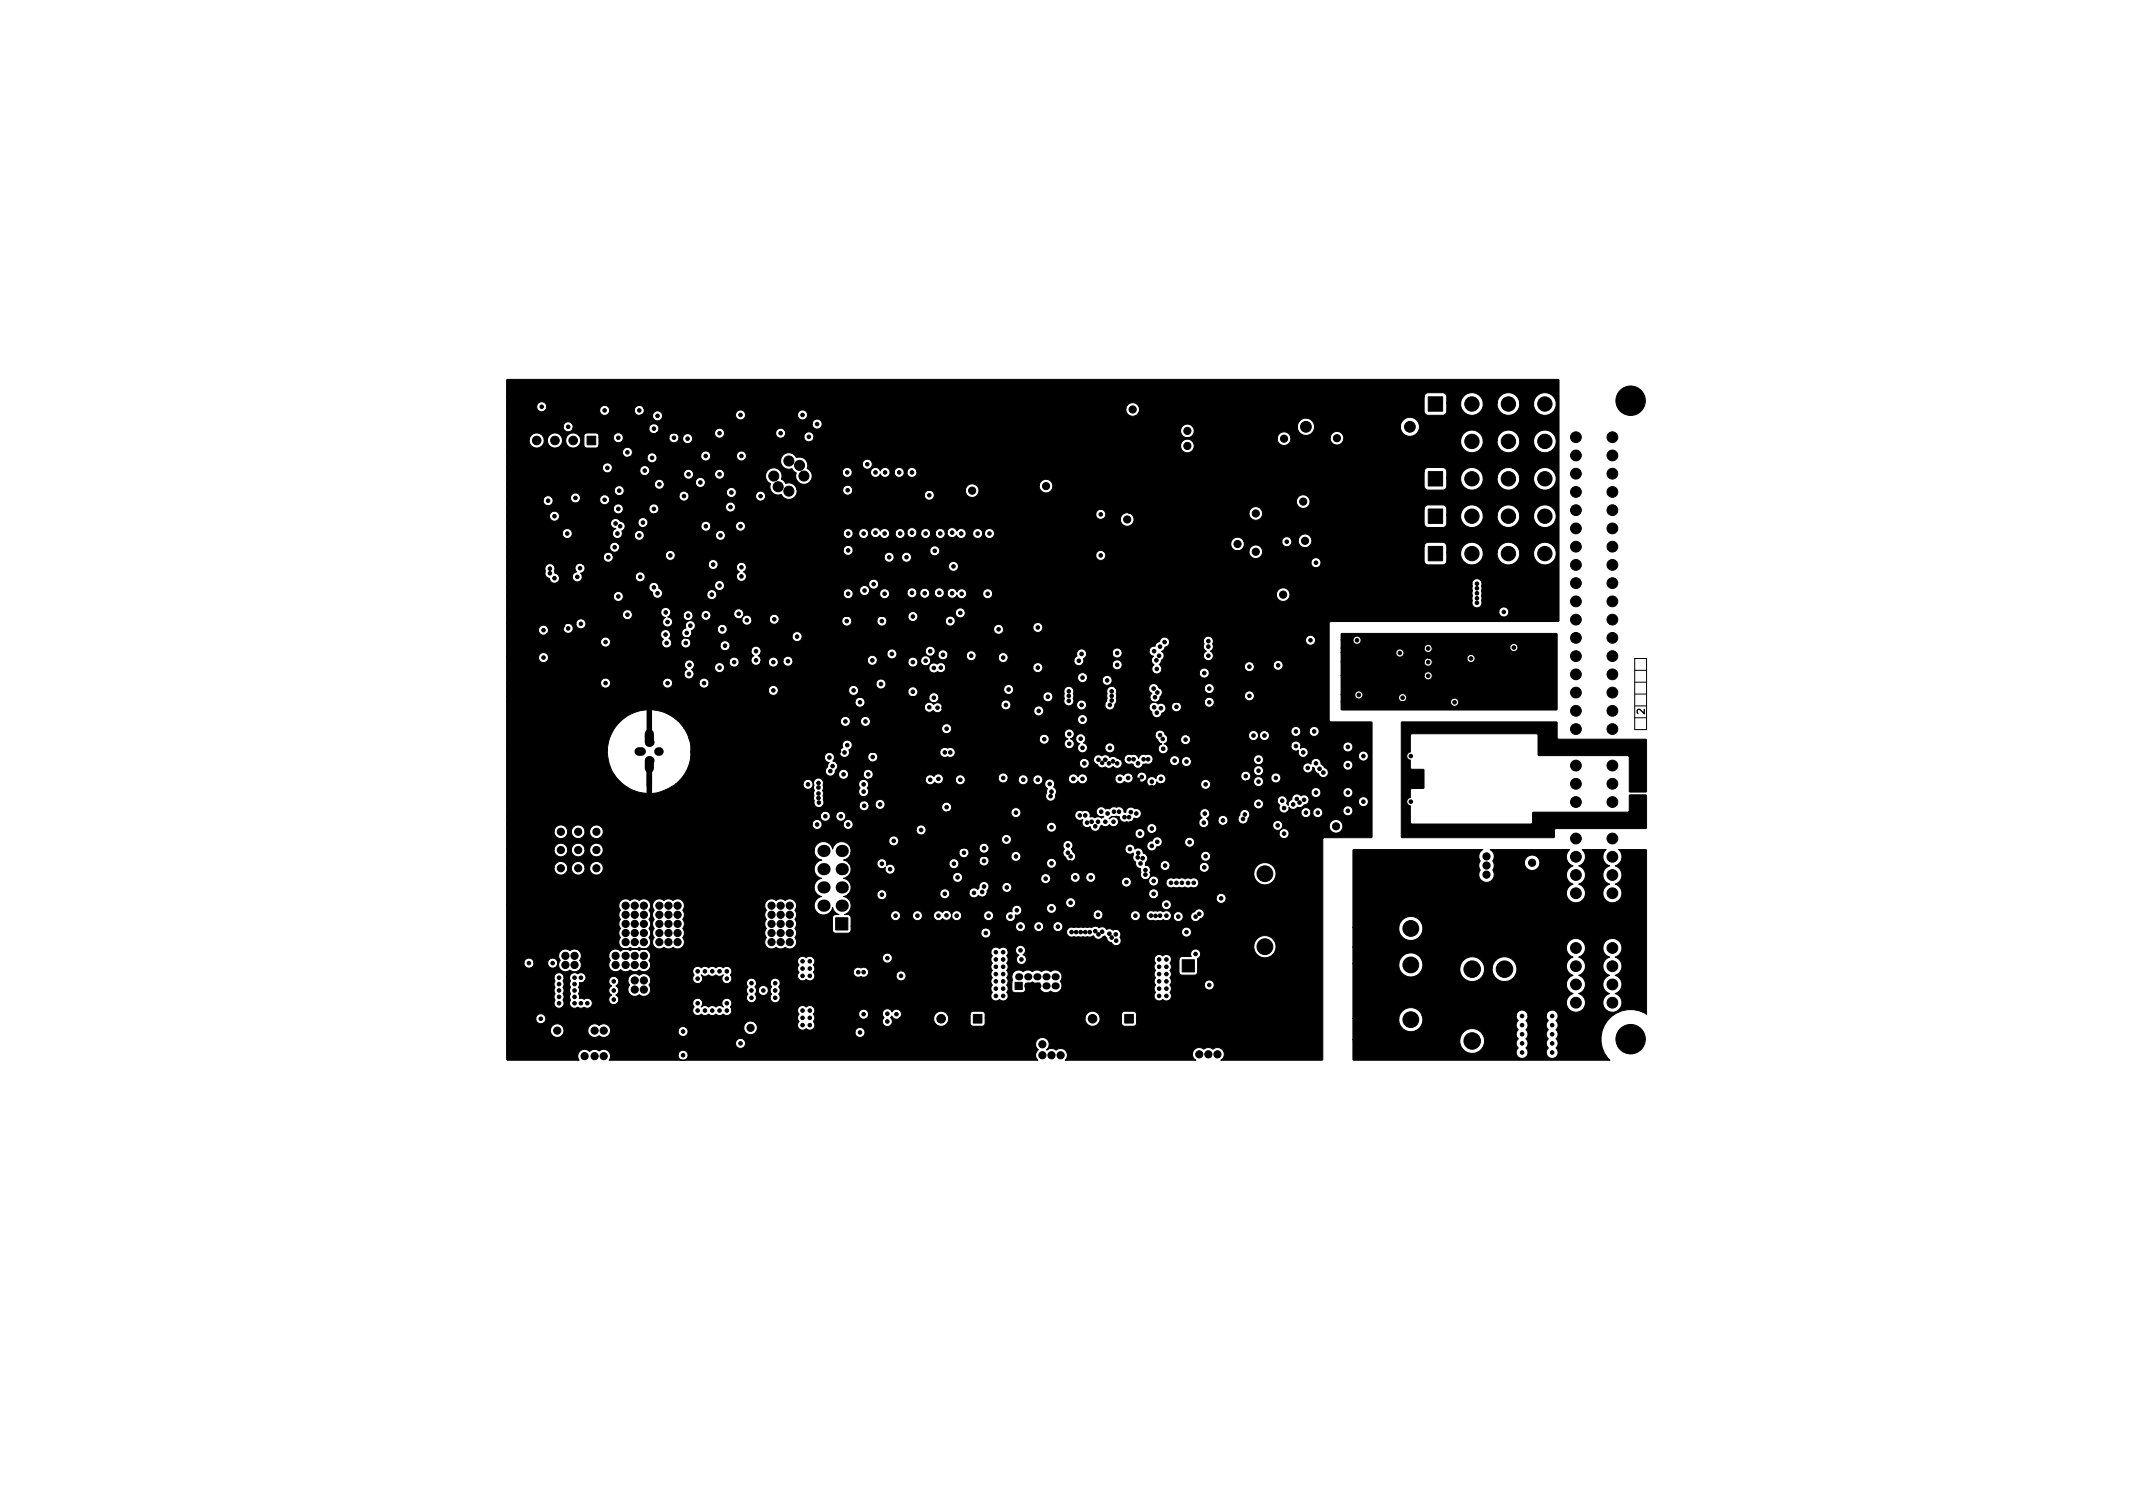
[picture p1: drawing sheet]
<svg xmlns="http://www.w3.org/2000/svg" width="297mm" height="210mm" viewBox="0 0 297 210" stroke-linecap="round" stroke-linejoin="round" font-family="sans-serif">
<defs><g id="words">
<text font-size="1.4" x="229" y="99.4" transform="rotate(-90 229 99.4)">2</text>
</g></defs>
<g fill="#000" stroke="#000" stroke-width=".14">
<path d="M198.9 55.3h2v2h-2zM70.5 52.9l.1-.1h146.4l.1 .1v33.6h-.1h-31.7l-.2 .2v13.6l.2 .2h5.7l.1 .1v16h-.1h-6.6l-.2 .2v30.7l-.1 .1h-14.1a.97 .97 0 0 0 .3-1.4 .97 .97 0 0 0-1.4-.1 1.05 1.05 0 0 0-1.3 0 .95 .95 0 0 0-1.4 .2 .95 .95 0 0 0 .3 1.3h-18.2l.1-.1a.97 .97 0 0 0-.1-1.3 .97 .97 0 0 0-1.3 0 1.05 1.05 0 0 0-1.2 0v-.1a.95 .95 0 0 0 0-1.4 .95 .95 0 0 0-1.3 .1 .95 .95 0 0 0 .1 1.4 .94 .94 0 0 0-.1 1.4h-59.7l.2-.3v-.4h9.4v.1a.7 .7 0 0 0 1.1 .5 .7 .7 0 0 0 0-1.2 .7 .7 0 0 0-1.1 .6h-9.4v-.1a1 1 0 0 0-1.6-.5 .94 .94 0 0 0-1.3 .1 .95 .95 0 0 0-1.3-.1 .95 .95 0 0 0-.1 1.3h-10.1l-.1-.1v-2.3h31.9a.7 .7 0 0 0 1 .7 .7 .7 0 0 0 .2-1.1 .7 .7 0 0 0-1.1 .3l-.1 .1h-31.9v-1.8h6.2a.95 .95 0 0 0 .9 1.1 .95 .95 0 0 0 .9-1.1h3.4v.2a.99 .99 0 0 0 1.6 .6 .95 .95 0 0 0 1 .2 .95 .95 0 0 0 .5-.8h9.4v.1a.7 .7 0 0 0 1.1 .5 .7 .7 0 0 0 0-1.2h8.1v.2a.95 .95 0 0 0 .7 .8 .95 .95 0 0 0 1-.3h13.8v.1a.7 .7 0 0 0 1 .6 .7 .7 0 0 0 0-1.2 .7 .7 0 0 0-1 .5h-13.8l.1-.1a.95 .95 0 0 0-.6-1.4 .95 .95 0 0 0-1.2 .8h-8.1a.7 .7 0 0 0-1.1 .6h-9.4v-.2a.99 .99 0 0 0-1.6-.6 .95 .95 0 0 0-1.5 .6h-3.4v-.2a.95 .95 0 0 0-1-.6 .95 .95 0 0 0-.8 .8h-6.2v-1.6h4.1v.1a.7 .7 0 0 0 1.1 .5 .7 .7 0 0 0 0-1.1 .7 .7 0 0 0-1.1 .5h-4.1v-5.7h6.7v.1a.53 .53 0 0 1 0 .8l.1 .5a.71 .71 0 0 0 0 .9 .7 .7 0 0 0 0 .9 .7 .7 0 0 0 .1 .9 .7 .7 0 0 0 .9 0 .7 .7 0 0 0 .1-1 .7 .7 0 0 0 0-.8 .7 .7 0 0 0 0-.9 .7 .7 0 0 0 0-.9l.1-.5h.8v.1a.53 .53 0 0 1 0 .8l.2 .5a.71 .71 0 0 0 0 .9 .7 .7 0 0 0 0 .9 .7 .7 0 0 0 0 .9 .7 .7 0 0 0 1 0 .7 .7 0 0 0 .8 0 .7 .7 0 0 0 1 0 .7 .7 0 0 0 0-1 .7 .7 0 0 0-1 0l-.3-.2h-.3v-.3l-.2-.3a.71 .71 0 0 0 0-.9l.2-.4v-.3a.69 .69 0 0 0 .7-.2h3.4l.1 .4 .3 .3a.69 .69 0 0 0-.4 .6 .69 .69 0 0 0 .4 .7 .7 .7 0 0 0-.3 1 .7 .7 0 0 0 1.1 0h10.5v.3l.2 .3a.7 .7 0 0 0 0 1 .7 .7 0 0 0 1 0 .69 .69 0 0 0 1 0 .69 .69 0 0 0 1 0 .69 .69 0 0 0 1 0 .7 .7 0 0 0 .8 .1 .7 .7 0 0 0 .4-.7h9.2v.3l.2 .3a.69 .69 0 0 0 0 1 .7 .7 0 0 0 0 1 .7 .7 0 0 0 1 0 .7 .7 0 0 0 1 0 .7 .7 0 0 0 0-1 .69 .69 0 0 0 0-1h6.3v.1a.7 .7 0 0 0 .8 .6 .7 .7 0 0 0 .6-.8h1.9v.3l.2 .3a.7 .7 0 0 0 0 1 .7 .7 0 0 0 1 0 .7 .7 0 0 0-.1-1l.2-.2a.69 .69 0 0 0 1.1 .3h4.7v.2a1.05 1.05 0 0 0 1.4 .8 1.05 1.05 0 0 0 .5-1.5h3.2v1.2a.45 .45 0 0 0 .4 .4l1.5-.1 .2-.3v-.7h13.9v.2a1.05 1.05 0 0 0 1.4 .8 1.05 1.05 0 0 0 .5-1.5h3.2v1.2a.45 .45 0 0 0 .4 .4h1.2l.3-.1 .2-.3v-1.2a.45 .45 0 0 0-.5-.5h-1.3l-.2 .1-.1 .4h-3.2a1.05 1.05 0 0 0-1.1-.5 1.05 1.05 0 0 0-.8 1h-13.9v-.5a.45 .45 0 0 0-.5-.5h-1.2l-.3 .1-.1 .4h-3.2a1.05 1.05 0 0 0-1.1-.5 1.05 1.05 0 0 0-.8 1h-4.7l.1-.1a.7 .7 0 0 0-.2-1.1 .7 .7 0 0 0-1 .3 .7 .7 0 0 0-.7-.4 .7 .7 0 0 0-.6 .6h-1.9l-.1-.1a.7 .7 0 0 0-.7-.5 .7 .7 0 0 0-.6 .7h-6.3l.1-.2a.7 .7 0 0 0-.2-.9 .7 .7 0 0 0-.9 .1 .7 .7 0 0 0-.8-.2 .7 .7 0 0 0-.4 .6h-9.2l-.2-.4 .1-.1a.7 .7 0 0 0-.1-.9 .7 .7 0 0 0-1 0 .7 .7 0 0 0 0 1 .78 .78 0 0 0-1 0 .69 .69 0 0 0-1 0 .78 .78 0 0 0-1.1 0 .7 .7 0 0 0-.1-1.1 .7 .7 0 0 0-1 .5h-10.5l.1-.1a.69 .69 0 0 0-.3-.9 .69 .69 0 0 0 .4-.7 .69 .69 0 0 0-.4-.6 .69 .69 0 0 0 .3-.9h1.3l.1 .4 .2 .4a.97 .97 0 0 0 0 1.3 .97 .97 0 0 0 1.4 0 .97 .97 0 0 0 1.3-.1 .97 .97 0 0 0 0-1.3 .97 .97 0 0 0-.1-1.3 .97 .97 0 0 0-1.3 0 .95 .95 0 0 0-1.6 .6h-1.3v-.1a.7 .7 0 0 0-.8-.3 .7 .7 0 0 0-.5 .6h-3.4l.1-.1a.7 .7 0 0 0-.2-.9 .7 .7 0 0 0-.8 0 .7 .7 0 0 0-1.2 .5h-.8v-.2a.7 .7 0 0 0-.7-.5 .7 .7 0 0 0-.6 .7h-6.7v-2.1h2.5v.2a.7 .7 0 0 0 .7 .6 .7 .7 0 0 0 .7-.8h1.9v.2a.7 .7 0 0 0 1 .5 .7 .7 0 0 0 0-1.2 .7 .7 0 0 0-1 .5h-1.9l-.1-.1a.7 .7 0 0 0-.7-.5 .7 .7 0 0 0-.6 .6h-2.5v-1h7.3v.4l.2 .3a.97 .97 0 0 0 .1 1.3 .97 .97 0 0 0 1.3 .1 .97 .97 0 0 0 1.3-.1 .97 .97 0 0 0 0-1.3l.2-.3 .1-.4h3.8v.4l.2 .3a.95 .95 0 0 0 .1 1.4 .95 .95 0 0 0 1.3-.1 1.04 1.04 0 0 0 1.4 .1 1.05 1.05 0 0 0 1.3 0l.5 .2 .5-.1h6.4v.3l.2 .3h-.1a.7 .7 0 0 0 .1 1 .7 .7 0 0 0 1-.1 .7 .7 0 0 0-.1-.9 .78 .78 0 0 0 1.1-.1 .69 .69 0 0 0 1 0 .78 .78 0 0 0 1 .1 .69 .69 0 0 0 0 .9 .69 .69 0 0 0 .9 .1h2.4v.3l.2 .3a.69 .69 0 0 0 0 1 .7 .7 0 0 0-.1 1 .7 .7 0 0 0 1 0 .7 .7 0 0 0 0-1l.2-.3v-.3h.3a.7 .7 0 0 0 .9 .8 .7 .7 0 0 0 .3-1.2 .7 .7 0 0 0-1.2 .3v.1h-.3l-.2-.4 .2-.3v-.3h2v.3l.2 .3-.1 .1a.69 .69 0 0 0 .1 .9 .7 .7 0 0 0 0 1 .7 .7 0 0 0 .9 0 .7 .7 0 0 0 0-1 .69 .69 0 0 0 0-1 .7 .7 0 0 0-.1-1.1 .7 .7 0 0 0-1 .5h-2v-.1a.7 .7 0 0 0-.7-.5 .7 .7 0 0 0-.6 .6h-2.3a.69 .69 0 0 0 0-1 .7 .7 0 0 0 0-1 .7 .7 0 0 0-1 0 .69 .69 0 0 0-1 0 .69 .69 0 0 0-1 0 .69 .69 0 0 0-1 0 .7 .7 0 0 0-.8-.2 .7 .7 0 0 0-.4 .6h-6.4l.2-.1a.94 .94 0 0 0 .1-1.3h20.7v.3l.2 .3a.69 .69 0 0 0 0 1 .7 .7 0 0 0 0 1 .7 .7 0 0 0 1 0 .7 .7 0 0 0 1 0 .7 .7 0 0 0 0-1l5.5-.1v.1a.76 .76 0 0 0 1.1 .6 .7 .7 0 0 0 .9-.2h4v.2a.7 .7 0 0 0 1 .5 .7 .7 0 0 0 0-1.2 .7 .7 0 0 0-1 .5h-4l.1-.1a.73 .73 0 0 0-.2-.9 .73 .73 0 0 0-.9 0 .7 .7 0 0 0-1 .5h-5.5l.2-.5-.2-.4v-.1a.69 .69 0 0 0-.1-1h9.7v.2a.7 .7 0 0 0 1 .5 .7 .7 0 0 0 0-1.2 .7 .7 0 0 0-1 .5h-9.7a.69 .69 0 0 0-.9 .1 .7 .7 0 0 0-.8-.2 .7 .7 0 0 0-.4 .6h-20.7a1.1 1.1 0 0 0 0-1.3h47.6v.3l.2 .3a.69 .69 0 0 0 0 1 .69 .69 0 0 0 0 1 .69 .69 0 0 0 0 1 .69 .69 0 0 0 0 1.1 .69 .69 0 0 0 0 1 .7 .7 0 0 0 0 1 .7 .7 0 0 0 1 0 .7 .7 0 0 0 1 0 .7 .7 0 0 0 0-1 .69 .69 0 0 0 0-1l.2-.4h.5v1a.45 .45 0 0 0 .5 .4h1l.3-.1 .1-.2v-1a1.15 1.15 0 0 0 1-.2l.5 .3 .5-.1a.98 .98 0 0 0 .3 1.1 .98 .98 0 0 0 1.2 0 .97 .97 0 0 0 1.3-.1 .97 .97 0 0 0 .1-1.3 .97 .97 0 0 0-.1-1.3 .97 .97 0 0 0-1.3 0 1.05 1.05 0 0 0-1.3 0 1.05 1.05 0 0 0-1.3 0 1.05 1.05 0 0 0-1.2 0 .99 .99 0 0 0-1.3 0 .99 .99 0 0 0-.2 1.2l-.1 .3h-.5v-.4l-.2-.3a.69 .69 0 0 0 0-1 .69 .69 0 0 0 0-1 .69 .69 0 0 0 0-1l.2-.4-.1-.4h1.1l.1 .4 .4 .3-.1 .1a.7 .7 0 0 0 .2 1.1 .7 .7 0 0 0 .9-.7h17.8v.3l.2 .3a.69 .69 0 0 0 0 1 .69 .69 0 0 0 0 1 .69 .69 0 0 0 0 1.1 .69 .69 0 0 0 0 1 .7 .7 0 0 0 0 1 .7 .7 0 0 0 1 0 .7 .7 0 0 0 1 0 .7 .7 0 0 0 0-1 .69 .69 0 0 0 0-1l4.8-.1v.1a.7 .7 0 0 0 1.1 .5 .7 .7 0 0 0 0-1.1 .7 .7 0 0 0-1.1 .5h-4.7l.1-.5-.2-.5h.1a.69 .69 0 0 0-.1-1 .69 .69 0 0 0 0-1l.2-.5h1.1v1.7l.1 .4 .3 .1h1.7a.45 .45 0 0 0 .5-.5v-1.7a.71 .71 0 0 0 .4-.9 .71 .71 0 0 0-.9-.5 .71 .71 0 0 0-.5 .8l.1 .2h-1.4l-.2 .2-.1 .2h-1.1a.69 .69 0 0 0-.4-.6 .69 .69 0 0 0-.8 .1 .7 .7 0 0 0-.7-.2 .7 .7 0 0 0-.5 .6h-17.8l-.1-.3-.3-.3h.1a.7 .7 0 0 0-.2-1.2 .7 .7 0 0 0-1 .6h-1.1a.69 .69 0 0 0-1.1-.2 .7 .7 0 0 0-.7-.2 .7 .7 0 0 0-.5 .6h-47.6a1.04 1.04 0 0 0-1.4-.1 1.05 1.05 0 0 0-1.3 0 .94 .94 0 0 0-1.3 .1 .95 .95 0 0 0-1-.3 .95 .95 0 0 0-.6 .8h-3.8l-.1-.2a1 1 0 0 0-1.6-.4 .95 .95 0 0 0-1.5 .6h-7.3v-7h15.7v.4l.2 .3a1.04 1.04 0 0 0 0 1.3 1.05 1.05 0 0 0 0 1.3 1.05 1.05 0 0 0 0 1.3 .97 .97 0 0 0 .1 1.3 .97 .97 0 0 0 1.3 0 1.05 1.05 0 0 0 1.3 0 .97 .97 0 0 0 1.3-.1 .97 .97 0 0 0 0-1.3 1.05 1.05 0 0 0 0-1.3 1.05 1.05 0 0 0 0-1.2 1.05 1.05 0 0 0 0-1.3l.2-.3v-.4h.3v.4l.2 .3a1.04 1.04 0 0 0 0 1.3 1.05 1.05 0 0 0 0 1.3 1.05 1.05 0 0 0 0 1.3 .97 .97 0 0 0 .1 1.3 .97 .97 0 0 0 1.3 0 1.05 1.05 0 0 0 1.3 0 .97 .97 0 0 0 1.3-.1 .97 .97 0 0 0 0-1.3 1.05 1.05 0 0 0 0-1.3 1.05 1.05 0 0 0 0-1.2 1.05 1.05 0 0 0 0-1.3l.2-.3v-.4h11.2v.4l.2 .3a1.04 1.04 0 0 0 0 1.3 1.05 1.05 0 0 0 0 1.3 1.05 1.05 0 0 0 0 1.3 .97 .97 0 0 0 .1 1.3 .97 .97 0 0 0 1.3 0 1.05 1.05 0 0 0 1.3 0 .97 .97 0 0 0 1.3-.1 .97 .97 0 0 0 0-1.3 1.05 1.05 0 0 0 0-1.3 1.05 1.05 0 0 0 0-1.2 1.05 1.05 0 0 0 0-1.3 .97 .97 0 0 0-.1-1.3 .97 .97 0 0 0-1.3 0 1.05 1.05 0 0 0-1.3 0 .95 .95 0 0 0-1.5 .6h-11.2v-.2a1 1 0 0 0-1.6-.4 1.05 1.05 0 0 0-1.3 0 .95 .95 0 0 0-1.5 .6h-.3v-.2a1 1 0 0 0-1.6-.4 1.05 1.05 0 0 0-1.3 0 .95 .95 0 0 0-1.5 .6h-15.7v-5.2h6.7v.2a.95 .95 0 0 0 1 .8 .95 .95 0 0 0 .8-1h.6v.2a.95 .95 0 0 0 1 .8 .95 .95 0 0 0 .9-1h.6v.2a.95 .95 0 0 0 1.5 .7 .95 .95 0 0 0 0-1.6 .95 .95 0 0 0-1.5 .7h-.6l-.1-.2a.95 .95 0 0 0-1-.6 .95 .95 0 0 0-.8 .8h-.6v-.2a.95 .95 0 0 0-1-.6 .95 .95 0 0 0-.8 .8h-6.7v-2.5h6.7v.2a.95 .95 0 0 0 1 .8 .95 .95 0 0 0 .8-1h.6v.2a.95 .95 0 0 0 1 .8 .95 .95 0 0 0 .9-1h.6v.2a.95 .95 0 0 0 1 .8 .95 .95 0 0 0 .9-.9h29.4l.1 .7 .4 .4 .5 .3h-.1a1.3 1.3 0 0 0-.9 1.3 1.3 1.3 0 0 0 1 1.2 1.29 1.29 0 0 0-1 1.3 1.29 1.29 0 0 0 1 1.2 1.3 1.3 0 0 0-.6 2.2 1.3 1.3 0 0 0 2.2-.6l.2 .5 .6 .4-.6 .1-.2 .2-.1 1.9a.45 .45 0 0 0 .5 .4h1.7l.2-.1h18.3a.7 .7 0 0 0 .9 .8 .7 .7 0 0 0 .3-1.2 .7 .7 0 0 0-1.2 .3v.1h-18.3l.2-.2v-.6h22.9v.1a.7 .7 0 0 0 .8 .6 .7 .7 0 0 0 .6-.7h1.2v.1a.7 .7 0 0 0 .7 .6 .7 .7 0 0 0 .6-.7h1.3v.1a.7 .7 0 0 0 .8 .6h1.1v.2a.7 .7 0 0 0 1 .5l2.3 .1 .4-.2a.75 .75 0 0 0 .7 .5 .75 .75 0 0 0 .7-.4l.3-.1 .2 .3a.84 .84 0 0 0 .7 .7l.2 .2 .4 .2h19.2a1.55 1.55 0 0 0 2.1 1.6 1.55 1.55 0 0 0 .5-2.6 1.55 1.55 0 0 0-2.5 .7l-.1 .3h-19a.69 .69 0 0 0 .4-1.2l.1-.3-.1-.5h8.5a.7 .7 0 0 0 1 .7 .7 .7 0 0 0 .2-1.1 .7 .7 0 0 0-1.1 .3l-.1 .1h-8.5a.69 .69 0 0 0-1-.2 .68 .68 0 0 0-.9-.1 .69 .69 0 0 0-1.1-.2 .69 .69 0 0 0-1 0l-2.2-.1-.3 .1a.7 .7 0 0 0-1 .5h-1.1h.1a.7 .7 0 0 0 .3-1.2 .7 .7 0 0 0-1.2 .5h-1.3v-.2a.7 .7 0 0 0-.7-.5 .7 .7 0 0 0-.6 .7h-1.2v-.2a.7 .7 0 0 0-.8-.5 .7 .7 0 0 0-.6 .7h-22.9v-1.3l-.2-.3h5.7a.7 .7 0 0 0 .7 .8 .7 .7 0 0 0 .7-.8h1.7v.2a.7 .7 0 0 0 .7 .6 .7 .7 0 0 0 .7-.8h1.5v.2a.7 .7 0 0 0 .5 .6 .7 .7 0 0 0 .8-.3 .72 .72 0 0 0 .8 .2 .72 .72 0 0 0 .4-.7 .7 .7 0 0 0 .7 .8 .7 .7 0 0 0 .7-.8h3.1v.2a.7 .7 0 0 0 .7 .6 .7 .7 0 0 0 .7-.6h1.6v.1a.7 .7 0 0 0 .9 .6 .7 .7 0 0 0 .5-.9h.3l.3-.1h10.2v.1a.7 .7 0 0 0 .7 .7 .7 .7 0 0 0 .7-.7h3.8v.2a.7 .7 0 0 0 .8 .6 .7 .7 0 0 0 .6-.8h.8v.2a.71 .71 0 0 0 1 .5l.4 .1 .3-.1a.7 .7 0 0 0 .7-.1 .7 .7 0 0 0 1.1-.4h.3v.1a.7 .7 0 0 0 .8 .6 .7 .7 0 0 0 .6-.7h1v.1a.74 .74 0 0 0 .6 .6 .74 .74 0 0 0 .8-.4 .7 .7 0 0 0 .3-1.1 .7 .7 0 0 0-1.1 .1l-.4 .3-.2 .4h-1a.7 .7 0 0 0-.7-.7 .7 .7 0 0 0-.7 .7h-.3v-.2a.7 .7 0 0 0-1.1-.4l-.4-.2-1 .1a.7 .7 0 0 0-1 .5h-.8v-.1a.7 .7 0 0 0-.8-.5 .7 .7 0 0 0-.6 .6h-3.8v-.1a.7 .7 0 0 0-.7-.6 .7 .7 0 0 0-.7 .6h-10.2l.3-.4-.1-.5h3.5a.7 .7 0 0 0 1 .7 .7 .7 0 0 0 .2-1.1 .7 .7 0 0 0-1.1 .3l-.1 .1h-3.5a.7 .7 0 0 0-.9-.3 .7 .7 0 0 0-.3 .9 .69 .69 0 0 0-1 .6h-1.6v-.2a.7 .7 0 0 0-.7-.6 .7 .7 0 0 0-.7 .6h-3.1v-.1a.72 .72 0 0 0-.8-.5 .72 .72 0 0 0-.6 .6 .69 .69 0 0 0-.5-.6 .69 .69 0 0 0-.8 .3 .7 .7 0 0 0-.7-.3 .7 .7 0 0 0-.5 .6h-1.5l-.1-.1a.7 .7 0 0 0-.7-.5 .7 .7 0 0 0-.6 .6h-1.7v-.1a.7 .7 0 0 0-.8-.5 .7 .7 0 0 0-.6 .6h-5.7l-.7-.1a1.29 1.29 0 0 0 .8-1.7h30v.2a.7 .7 0 0 0 .6 .6 .7 .7 0 0 0 .8-.5h11.9v.1a.7 .7 0 0 0 1.1 .6 .7 .7 0 0 0 0-1.2 .7 .7 0 0 0-1.1 .5h-11.9a.7 .7 0 0 0-.6-.9 .7 .7 0 0 0-.8 .6h-30l-.4-.5-.5-.3 .6-.3h4a.7 .7 0 0 0 .8 .8 .7 .7 0 0 0 .6-.9h7.4v.1a.7 .7 0 0 0 .8 .6 .7 .7 0 0 0 .5-.8h2.7v.1a.7 .7 0 0 0 .6 .6 .7 .7 0 0 0 .8-.3 .69 .69 0 0 0 1.2-.3h22.5v.1a.69 .69 0 0 0 1.1 .5h8.3v.2a.7 .7 0 0 0 1 .5 .7 .7 0 0 0 0-1.2 .7 .7 0 0 0-1 .5h-8.3a.7 .7 0 0 0-.1-1.2 .7 .7 0 0 0-1 .6h-22.5l-.1-.4 .3-.5h1.8a.7 .7 0 0 0 1 .7 .7 .7 0 0 0 .2-1.1 .7 .7 0 0 0-1.2 .3v.1h-1.8a.71 .71 0 0 0-.8-.7 .71 .71 0 0 0-.6 .9l-.1 .2-.1-.1a.7 .7 0 0 0-1.2 .5h-2.7a.7 .7 0 0 0-.7-.5 .7 .7 0 0 0-.6 .6h-7.4a.7 .7 0 0 0-.8-.5 .7 .7 0 0 0-.6 .6h-4l.1-.1a1.29 1.29 0 0 0-.7-2.1l.4-.2h14.8a.7 .7 0 0 0 .6 .8 .7 .7 0 0 0 .7-.6h10.9v.1a.7 .7 0 0 0 .9 .6 .7 .7 0 0 0 .5-.9h2.7v.1a.7 .7 0 0 0 .8 .7 .7 .7 0 0 0 .6-.8h.8v.1a.69 .69 0 0 0 1.1 .6h3.9v.1a.7 .7 0 0 0 .8 .6 .7 .7 0 0 0 .5-.9h2.5v.1a.7 .7 0 0 0 .6 .7 .7 .7 0 0 0 .7-.5h1.1v.1a.76 .76 0 0 0 1.1 .5l.3 .1a.94 .94 0 0 1 .9 0l.3-.1 .5 .1 .4-.1a.72 .72 0 0 0 1-.7 .72 .72 0 0 0-1.1-.5h-.6a.27 .27 0 0 1-.4 0h-.6l-.3-.1a.94 .94 0 0 1-.9 0l-.5 .3-.1 .4h-1.1a.7 .7 0 0 0-.5-.9 .7 .7 0 0 0-.8 .6h-2.5v-.1a.7 .7 0 0 0-.8-.4 .7 .7 0 0 0-.5 .7h-3.9v-.1a.7 .7 0 0 0-.1-1.1 .7 .7 0 0 0-1 .5h-.8v-.1a.7 .7 0 0 0-.7-.5 .7 .7 0 0 0-.7 .6h-2.7l-.1-.1a.7 .7 0 0 0-.7-.3 .7 .7 0 0 0-.6 .6l-10.9-.1a.7 .7 0 0 0-.6-.7 .7 .7 0 0 0-.7 .6h-14.8l.1-.1a1.3 1.3 0 0 0 .2-1.8h3.9v.1a.7 .7 0 0 0 .5 .6 .7 .7 0 0 0 .7-.2 .7 .7 0 0 0 .6 1 .7 .7 0 0 0 .7-1 .7 .7 0 0 0-1.2-.1l.1-.4h8.6a.7 .7 0 0 0 .9 .7 .7 .7 0 0 0 .4-1.1h2.9v.2a.7 .7 0 0 0 .6 .6 .7 .7 0 0 0 .8-.5h8v.2a.7 .7 0 0 0 1.1 .5 .7 .7 0 0 0 0-1.2 .7 .7 0 0 0-1.1 .5h-8a.7 .7 0 0 0-.5-.9 .7 .7 0 0 0-.9 .6h-2.9l-.1-.1a.7 .7 0 0 0-1.2 .5h-8.6v-.1a.7 .7 0 0 0-.8-.5 .7 .7 0 0 0-.6 .6h-3.9l-.4-.3-.3-.1 .3-.2 .4-.3 .3-.6h15v.1a.7 .7 0 0 0 .5 .6 .7 .7 0 0 0 .8-.2h6v.1a.7 .7 0 0 0 1 .5 .7 .7 0 0 0 0-1.1 .7 .7 0 0 0-1 .5h-6l.1-.1a.7 .7 0 0 0-.5-1 .7 .7 0 0 0-.9 .6h-15l-.1-.7h17.9a.7 .7 0 0 0 .9 .8 .7 .7 0 0 0 .4-1.1h10.4v.2l.2 .3a.78 .78 0 0 0 .2 1.3 .7 .7 0 0 0 1.1 .3 .7 .7 0 0 0-.1-1.2l-.2-.4h.1h7.4v.1a.7 .7 0 0 0 1.1 .5v.2a.75 .75 0 0 0 .4 1 .69 .69 0 0 0 .7 .9l-.1 .7a.7 .7 0 0 0 .8 .9 .7 .7 0 0 0 .5-1h14.5v.3a1.55 1.55 0 0 0 2.4 1.2 1.55 1.55 0 0 0 0-2.7 1.55 1.55 0 0 0-2.4 1.2h-14.5a.69 .69 0 0 0-.6-1l2.1-.1a.7 .7 0 0 0 .5 .8 .7 .7 0 0 0 .8-.5h4.1v.1a.7 .7 0 0 0 1.1 .6 .7 .7 0 0 0 0-1.2 .7 .7 0 0 0-1.1 .5h-4.1v-.1a.7 .7 0 0 0-.6-.8 .7 .7 0 0 0-.7 .6h-2.1v-.2a.84 .84 0 0 0 .2-1h7.5v.1a.7 .7 0 0 0 1.1 .5 .7 .7 0 0 0 0-1.2 .7 .7 0 0 0-1.1 .6h-7.5l-.2-.3-.3-.1v-.1a.7 .7 0 0 0-1.2-.5l-.2-.5h1.9a.7 .7 0 0 0 .6 .8 .7 .7 0 0 0 .8-.6 .69 .69 0 0 0 .8-.7h3.1v.1a.7 .7 0 0 0 1 .6 .7 .7 0 0 0 0-1.2 .7 .7 0 0 0-1 .5l-3.1-.1a.7 .7 0 0 0-.7-.6 .7 .7 0 0 0-.7 .6 .7 .7 0 0 0-.8 .6h-1.9a.7 .7 0 0 0-1.1 .5h-7.4v-.1a.7 .7 0 0 0-.4-1 .7 .7 0 0 0-.9 .6h-10.4l-.1-.1a.7 .7 0 0 0-1.2 .4h-17.9v-.1a1.3 1.3 0 0 0-1.4-.7 1.3 1.3 0 0 0-1 1 1.3 1.3 0 0 0-1.4-1 1.3 1.3 0 0 0-1.2 1.2h-29.4v-.1a.95 .95 0 0 0-.9-.9 .95 .95 0 0 0-1 .9h-.6l-.1-.2a.95 .95 0 0 0-1-.7 .95 .95 0 0 0-.8 .9h-.6v-.2a.95 .95 0 0 0-1-.7 .95 .95 0 0 0-.8 .9h-6.7v-1.3h53.3v.2a.7 .7 0 0 0 .8 .6 .7 .7 0 0 0 .5-1h14.4v.2a.7 .7 0 0 0 1 .5 .7 .7 0 0 0 0-1.2 .7 .7 0 0 0-1 .5h-14.4a.7 .7 0 0 0-.8-.4 .7 .7 0 0 0-.5 .6h-53.3v-1.3h6.7v.2a.95 .95 0 0 0 1 .9 .95 .95 0 0 0 .8-1.1h.6v.2a.95 .95 0 0 0 1 .9 .95 .95 0 0 0 .9-1.1h.6v.2a.95 .95 0 0 0 1.5 .7 .95 .95 0 0 0 0-1.6 .95 .95 0 0 0-1.5 .7h-.6l-.1-.2a.95 .95 0 0 0-1-.6 .95 .95 0 0 0-.8 .8h-.6v-.2a.95 .95 0 0 0-1-.6 .95 .95 0 0 0-.8 .8h-6.7v-1h42.6v.2a.7 .7 0 0 0 .8 .6 .7 .7 0 0 0 .6-.8h2.9v.2a.7 .7 0 0 0 .8 .6h9.4v.1a.7 .7 0 0 0 .5 .6 .7 .7 0 0 0 .7-.2h29.3v.1a.7 .7 0 0 0 1 .6 .7 .7 0 0 0 0-1.2 .7 .7 0 0 0-1 .5h-29.3l.2-.5-.2-.4h16.9a.7 .7 0 0 0 1 .7 .7 .7 0 0 0 .2-1.1 .7 .7 0 0 0-1.1 .3l-.1 .1h-16.9a.7 .7 0 0 0-.7-.2 .7 .7 0 0 0-.5 .6h-9.4h.1a.7 .7 0 0 0 .3-1.2 .7 .7 0 0 0-1.2 .4h-2.9v-.1a.7 .7 0 0 0-.8-.5 .7 .7 0 0 0-.6 .6h-42.6v-1.1h43.7v.1a.7 .7 0 0 0 .8 .7 .7 .7 0 0 0 .6-.8h.8v.1a.7 .7 0 0 0 1.1 .6 .7 .7 0 0 0 0-1.2 .7 .7 0 0 0-1.1 .5h-.8v-.1a.7 .7 0 0 0-.7-.5 .7 .7 0 0 0-.7 .6h-43.7v-9.2h14.1v.9l.3 1.2 .4 1 .7 .9 .9 .9 .9 .6 1 .4 1 .1 .8 .1 1.1-.2 1.3-.5 1.1-.7h17.7a.7 .7 0 0 0 .8 .8 .7 .7 0 0 0 .6-.9h.1l.1 .3-.1 .6a.26 .26 0 0 1 0 .4v.9l.1 .3a.69 .69 0 0 0 .3 .9 .69 .69 0 0 0 .9-.3h5v.2a.7 .7 0 0 0 .9 .6 .7 .7 0 0 0 .5-1h.9v.2a.7 .7 0 0 0 .5 .6 .7 .7 0 0 0 .8-.4h7.9v.2a.7 .7 0 0 0 .8 .6h8.9v.1a.7 .7 0 0 0 .5 .6 .7 .7 0 0 0 .8-.3h7.6v.1a.77 .77 0 0 0 1.1 .6 .7 .7 0 0 0 .1 .9 .7 .7 0 0 0 .9 0 .69 .69 0 0 0 .6 .6 .69 .69 0 0 0 .8-.4h6.5v.1a.69 .69 0 0 0 1 .6h17.4v.1a.7 .7 0 0 0 1.1 .6 .7 .7 0 0 0 0-1.2 .7 .7 0 0 0-1.1 .5h-17.4a.7 .7 0 0 0 .1-1.2 .7 .7 0 0 0-1.1 .5h-6.5a.28 .28 0 0 1 .2-.4 .28 .28 0 0 1 .3 .2h.4l.4-.2a.7 .7 0 0 0 1.1 0 .7 .7 0 0 0-.1-1 .7 .7 0 0 0-1 .1l-.1-.1a.92 .92 0 0 1 .9-.2l.2-.1 .4 .1a.7 .7 0 0 0 1 .7l.3 .1h9.7v.1a.7 .7 0 0 0 1 .6 .7 .7 0 0 0 .3-1h1.4v.1a.69 .69 0 0 0 1 .6h6.6v.1a.7 .7 0 0 0 .7 .6 .7 .7 0 0 0 .7-.6h6.5v.1a.95 .95 0 0 0 1.5 .8 .95 .95 0 0 0 0-1.6 .95 .95 0 0 0-1.5 .7h-6.5v-.1a.7 .7 0 0 0-.7-.7 .7 .7 0 0 0-.7 .7l-6.6-.1a.69 .69 0 0 0 .4-.8h1.4v.1a.7 .7 0 0 0 .8 .6 .7 .7 0 0 0 .6-.8 .7 .7 0 0 0-.2-1.1 .7 .7 0 0 0-.9 .7l-.3 .5-1.5-.1a.7 .7 0 0 0-.7-.4 .7 .7 0 0 0-.6 .7h-1.4l-.2-.3a.7 .7 0 0 0 .4-1 .7 .7 0 0 0-1.1-.1 .7 .7 0 0 0 .1 1.1l-.3 .2-.2 .4h-9.6l.4-.2 .2-.4a.7 .7 0 0 0 1-.6 .7 .7 0 0 0-.9-.7 .7 .7 0 0 0-.8-.2 .7 .7 0 0 0-.4 .7h-.3a.72 .72 0 0 0-1-.7 .69 .69 0 0 0-1 .3l-.6-.1a.7 .7 0 0 0-.9-.2 .7 .7 0 0 0-.2 1 .7 .7 0 0 0 .9 .3v.1l-.3 .1a.7 .7 0 0 0-.9 0l-.4-.2-.3 .1a.74 .74 0 0 0-.3-.8 .74 .74 0 0 0-.8-.1 .7 .7 0 0 0-1 .6h-7.6v-.1a.7 .7 0 0 0-.5-.9 .7 .7 0 0 0-.8 .6h-8.9h.1a.7 .7 0 0 0 .3-1.2h42.3v.1a.7 .7 0 0 0 1 .6 .7 .7 0 0 0 .1-1.2h2.2v.4l.3 .3a.69 .69 0 0 0 .1 .9 .69 .69 0 0 0 .9 .1h2v.1a.7 .7 0 0 0 .7 .6 .7 .7 0 0 0 .7-.7h.2v.1a.7 .7 0 0 0 .9 .6 .7 .7 0 0 0 .4-1h2.9v.2a.7 .7 0 0 0 1.1 .5 .7 .7 0 0 0 0-1.2 .7 .7 0 0 0-1.1 .5h-2.9a.7 .7 0 0 0-.7-.3 .7 .7 0 0 0-.6 .6h-.2l-.1-.2a.7 .7 0 0 0-.7-.4 .7 .7 0 0 0-.6 .6h-2l.3-.4v-.3a.69 .69 0 0 0 1.2 0 .84 .84 0 0 0 1-.3l.3-.2 .3-.3h6.9a.7 .7 0 0 0 .9 .7 .7 .7 0 0 0 .2-1.2 .7 .7 0 0 0-1.1 .3v.2h-6.9a.7 .7 0 0 0-.3-.8 .7 .7 0 0 0-.8 0 .71 .71 0 0 0-.9-.2 .71 .71 0 0 0-.4 .7 .69 .69 0 0 0-.5 .8l-.3-.2a.7 .7 0 0 0-.3-1.1 .7 .7 0 0 0-.9 .6h-2.2a.7 .7 0 0 0-1.1 .5l-42.3-.1a.7 .7 0 0 0-1.2 .5h-7.9v-.1a.7 .7 0 0 0-.5-.9 .7 .7 0 0 0-.8 .6h-1a.7 .7 0 0 0-.7-.4 .7 .7 0 0 0-.6 .6h-5l.1-.4-.1-.3 .1-1-.2-.3 .2-.4v-.6h4.9v.3l.2 .3-.1 .1a.7 .7 0 0 0 .1 1 .7 .7 0 0 0 1-.1 .7 .7 0 0 0-.1-1 .7 .7 0 0 0-.1-1.1 .7 .7 0 0 0-1 .5h-4.9a.7 .7 0 0 0-.6-.8 .7 .7 0 0 0-.8 .7l-.2-.1a.7 .7 0 0 0-.7-.4 .7 .7 0 0 0-.6 .6h-17.7l.9-.8 .6-1 .4-.9 .2-1h18.6v.1a.69 .69 0 0 0 .7 .7l-.2 .3v.3a.7 .7 0 0 0-.2 1.1 .7 .7 0 0 0 1.1-.2h.6v.2a.7 .7 0 0 0 .7 .6 .7 .7 0 0 0 .7-.8h2v.2a.7 .7 0 0 0 .8 .6h7.8v.1a.7 .7 0 0 0 .6 .7 .7 .7 0 0 0 .8-.4 .7 .7 0 0 0 .7 .2 .7 .7 0 0 0 .5-.6h1.6v.1a.7 .7 0 0 0 .9 .6 .7 .7 0 0 0 .4-.9h4.7v.1a.7 .7 0 0 0 .6 .6 .7 .7 0 0 0 .8-.5h1.4v.1a.7 .7 0 0 0 .8 .7 .7 .7 0 0 0 .6-.8h.6v.1a.7 .7 0 0 0 .5 .6 .7 .7 0 0 0 .7-.1h.5l.1 .4 .3 .3-.2 .7a.7 .7 0 0 0 .5 1.1 .7 .7 0 0 0 .8-.9l.1-.4h35.5v.1a.7 .7 0 0 0 .7 .7 .7 .7 0 0 0 .7-.8h3v.1a.7 .7 0 0 0 1.1 .5 .7 .7 0 0 0 0-1.1 .7 .7 0 0 0-1.1 .5h-3l-.1-.1a.7 .7 0 0 0-.7-.5 .7 .7 0 0 0-.6 .6h-35.5l-.1-.4-.3-.3a.7 .7 0 0 0-.3-1.1 .7 .7 0 0 0-.9 .6h-.5l.2-.3v-.4h3.6a.7 .7 0 0 0 .5 .7 .7 .7 0 0 0 .8-.4 .7 .7 0 0 0 .8 .4 .7 .7 0 0 0 .5-.7h3.9v.1a.7 .7 0 0 0 .5 .6 .7 .7 0 0 0 .8-.3 .7 .7 0 0 0 .8 .1 .7 .7 0 0 0 .4-.8h.5v.2a.69 .69 0 0 0 1.1 .5h.3v.1a.7 .7 0 0 0 .7 .6 .7 .7 0 0 0 .7-.7l.5 .3h5.6a.7 .7 0 0 0 .9 .8 .7 .7 0 0 0 .3-1.2 .7 .7 0 0 0-1.2 .3v.1h-5.5a.7 .7 0 0 0 .5-1.1h10.6v.1a.7 .7 0 0 0 .8 .7h1v.1a.7 .7 0 0 0 1 .5 .7 .7 0 0 0 0-1.1h1.4v.1a.7 .7 0 0 0 1 .5 .7 .7 0 0 0 0-1.2 .7 .7 0 0 0-1 .6l-1.4-.1a.7 .7 0 0 0-1 .6h-1l.1-.1a.7 .7 0 0 0 .2-1.2 .7 .7 0 0 0-1.1 .5h-10.6l-.1-.1a.69 .69 0 0 0-.7-.1 .69 .69 0 0 0-.4 .6 .7 .7 0 0 0-.8-.2 .7 .7 0 0 0-.5 .6l-.3-.1a.7 .7 0 0 0-.1-1.1 .7 .7 0 0 0-1 .5h-.5a.7 .7 0 0 0-.6-.5 .7 .7 0 0 0-.7 .4 .7 .7 0 0 0-.8-.2 .7 .7 0 0 0-.4 .6h-3.9v-.2a.7 .7 0 0 0-.6-.4 .7 .7 0 0 0-.7 .4 .7 .7 0 0 0-.7-.4 .7 .7 0 0 0-.6 .6h-3.6a.7 .7 0 0 0-.7-.5 .7 .7 0 0 0-.7 .6h-.6v-.1a.7 .7 0 0 0-.8-.5 .7 .7 0 0 0-.6 .6h-1.4v-.1a.7 .7 0 0 0-.6-.8 .7 .7 0 0 0-.8 .7h-4.7a.7 .7 0 0 0-.7-.4 .7 .7 0 0 0-.6 .6h-1.6v-.1a.7 .7 0 0 0-.6-.6 .7 .7 0 0 0-.7 .3 .7 .7 0 0 0-.8-.2 .7 .7 0 0 0-.5 .6h-7.8h.1a.69 .69 0 0 0 .5-.6 .69 .69 0 0 0-.3-.7h53.3v.2a.7 .7 0 0 0 .9 .6 .7 .7 0 0 0 .3-1.1h5.6v.1a.7 .7 0 0 0 .8 .6 .7 .7 0 0 0 .6-.8l.3 .2a.8 .8 0 0 0 .5 .8 .71 .71 0 0 0 1.2 .2 .71 .71 0 0 0-.4-1.2l-.2-.3h2.8v.1a.7 .7 0 0 0 1.1 .5 .7 .7 0 0 0 0-1.1 .7 .7 0 0 0-1.1 .5h-2.8l-.2-.1a.7 .7 0 0 0-.8-.8 .7 .7 0 0 0-.6 .8 .7 .7 0 0 0-1.2 .5h-5.6l-.1-.1a.7 .7 0 0 0-1.1 .4h-53.4a.7 .7 0 0 0-1 .5h-2l-.1-.1a.7 .7 0 0 0-.7-.5 .7 .7 0 0 0-.6 .6h-.6l.1-.4a.69 .69 0 0 0 .2-1.1h33.8v.2a.7 .7 0 0 0 1.1 .5 .7 .7 0 0 0 0-1.2h.9v.2a1 1 0 0 0 .6 .7 .7 .7 0 0 0 1 .2 .72 .72 0 0 0 1.1-.1 .7 .7 0 0 0 1.1 0 .7 .7 0 0 0-.3-1h.7v.1a.7 .7 0 0 0 1 .5l.3 .1a.71 .71 0 0 0 .7 .6 .71 .71 0 0 0 .7-.6h.5a.69 .69 0 0 0 .9-.6h2.3v.2a.7 .7 0 0 0 .7 .6 .7 .7 0 0 0 .7-.6h.2v.1a.7 .7 0 0 0 .9 .6 .7 .7 0 0 0 .4-1h8.8v.2a.7 .7 0 0 0 1 .5 .7 .7 0 0 0 0-1.2 .7 .7 0 0 0-1 .5h-8.8a.7 .7 0 0 0-.7-.3 .7 .7 0 0 0-.6 .6h-.2v-.2a.7 .7 0 0 0-.7-.6 .7 .7 0 0 0-.7 .6h-2.3a.7 .7 0 0 0-1-.7 .74 .74 0 0 0-1.1 .5 .69 .69 0 0 0-1-.5 .7 .7 0 0 0-1 .6l-.9-.1a.69 .69 0 0 0-1.1-.1 .76 .76 0 0 0-1.1-.3 .7 .7 0 0 0-1.1 .5h-1a.7 .7 0 0 0-1 .5h-33.8l-.5-.2a.7 .7 0 0 0-.2-1.2 .7 .7 0 0 0-1 .6h-18.6v-.7h20.7v.1a.69 .69 0 0 0 1.1 .5h2.8v.2a.7 .7 0 0 0 1.1 .5 .7 .7 0 0 0 0-1.2 .7 .7 0 0 0-1.1 .5h-2.8l.2-.2 .1-.4h12.6a.75 .75 0 0 0 1.1 .7 .72 .72 0 0 0 1-.7 .72 .72 0 0 0-1.1-.5 .7 .7 0 0 0-1 .5h-12.6l-.1-.3a.7 .7 0 0 0 .4-.9 .7 .7 0 0 0-.9-.4 .7 .7 0 0 0-.3 1l-.3 .2-.2 .4h-20.7v-.9l-.2-.9h48.7v.1a.7 .7 0 0 0 1.1 .5 .7 .7 0 0 0 0-1.2 .7 .7 0 0 0-1.1 .6h-48.7l-.7-1.5h35.8v.1a.7 .7 0 0 0 .9 .6h16.2l.1 .4 .4 .4a.7 .7 0 0 0-.4 1.1 .7 .7 0 0 0 1.2-.1 .7 .7 0 0 0-.4-1l.7-.1a.69 .69 0 0 0 .6 .7 .7 .7 0 0 0 0 1.3 .7 .7 0 0 0 1-.7h2.5v.1a.7 .7 0 0 0 1 .5 .7 .7 0 0 0 0-1.2 .7 .7 0 0 0-1 .6h-2.5l-.1-.4-.4-.2a.69 .69 0 0 0 0-1.2h9.9l.1 .4 .3 .3 .2 .3 .4 .3a.7 .7 0 0 0-.5 1 .7 .7 0 0 0 1.1 .3 .7 .7 0 0 0 .1-1.1h17.3v.1a.69 .69 0 0 0 1.1 .6 .7 .7 0 0 0 .2 .9 .7 .7 0 0 0 .9-.2h7.2v.1a.7 .7 0 0 0 1 .6 .7 .7 0 0 0 0-1.2 .7 .7 0 0 0-1 .5h-7.2l.1-.1a.7 .7 0 0 0-.2-.9 .7 .7 0 0 0-.8 0l.1-.3h5.8a.7 .7 0 0 0 1 .8 .7 .7 0 0 0 .2-1.2 .7 .7 0 0 0-1.2 .3v.1h-5.8a.7 .7 0 0 0-.7-.7 .7 .7 0 0 0-.7 .6h-17.3l-.4-.2 .4-.3 .1-.4h1.8a.7 .7 0 0 0 .6 .8 .7 .7 0 0 0 .8-.5 .7 .7 0 0 0-.4-.8h8.5v.1a.7 .7 0 0 0 .7 .6 .7 .7 0 0 0 .7-.7h.1v.1a.7 .7 0 0 0 1.1 .5 .7 .7 0 0 0-.1-1.2h3.4v.1a.7 .7 0 0 0 .7 .6 .7 .7 0 0 0 .7-.7h1.1v.1a.7 .7 0 0 0 1.1 .5 .7 .7 0 0 0 0-1.1 .7 .7 0 0 0-1.1 .5h-1.1l-.1-.2a.7 .7 0 0 0-.7-.4 .7 .7 0 0 0-.6 .6h-3.5a.7 .7 0 0 0-.9 .6h-.1l-.1-.2a.7 .7 0 0 0-.7-.5 .7 .7 0 0 0-.6 .7l-8.6-.1a.7 .7 0 0 0-.9 .6h-1.8l-.1-.3-.3-.3a.7 .7 0 0 0-.7-.6 .7 .7 0 0 0-.7 .6l-10-.1a.7 .7 0 0 0-1 .6h-.5v-.1a.7 .7 0 0 0-.1-1.1 .7 .7 0 0 0-1 .5h-16.2a.7 .7 0 0 0 .3-1.2 .7 .7 0 0 0-1.2 .5h-35.8l-.9-1h22.6v.1a.7 .7 0 0 0 .8 .6 .7 .7 0 0 0 .6-.7h1.4v.1a.7 .7 0 0 0 .9 .6 .7 .7 0 0 0 .4-1h29v.2a.7 .7 0 0 0 1 .5 .7 .7 0 0 0 0-1.2 .7 .7 0 0 0-1 .5h-29a.7 .7 0 0 0-.7-.3 .7 .7 0 0 0-.6 .6h-1.4v-.2a.7 .7 0 0 0-.7-.4 .7 .7 0 0 0-.7 .6h-22.6l-.9-.7-1-.5-1.6-.4h-.8l-1 .2-1.2 .4-.8 .5-.9 .7-.7 1-.5 .8-.3 .9-.1 1.1h-14.1v-6.7h48.6a.7 .7 0 0 0 1 .7h8.6v.2a.7 .7 0 0 0 .5 .6 .7 .7 0 0 0 .8-.3 .69 .69 0 0 0 1.1 0h12.9v.2a.7 .7 0 0 0 1 .5 .7 .7 0 0 0 0-1.2 .7 .7 0 0 0-1 .5h-12.9l.2-.4-.2-.4h8.3a.7 .7 0 0 0 .9 .7 .7 .7 0 0 0 .3-1.1 .7 .7 0 0 0-1.2 .3v.1h-8.3a.69 .69 0 0 0-1.1 0 .7 .7 0 0 0-.7-.3 .7 .7 0 0 0-.6 .6h-8.6a.7 .7 0 0 0 0-1.2 .7 .7 0 0 0-1 .5h-48.6v-.6h58.9v.1a.7 .7 0 0 0 .8 .6 .7 .7 0 0 0 .5-.8h14.5v.1a.7 .7 0 0 0 1.1 .5 .7 .7 0 0 0 0-1.2 .7 .7 0 0 0-1.1 .6l-14.5-.1a.7 .7 0 0 0-.7-.4 .7 .7 0 0 0-.6 .6h-58.9v-1h36.5v.1a.7 .7 0 0 0 .8 .6 .7 .7 0 0 0 .6-.7h9.8v.1a.7 .7 0 0 0 .6 .6 .7 .7 0 0 0 .8-.5h6.8v.1a.7 .7 0 0 0 1 .6 .7 .7 0 0 0 .3-1.1h12.1v.2a.7 .7 0 0 0 .6 .6 .7 .7 0 0 0 .7-.5h7l.1 1a.69 .69 0 0 0 .2 .9 .69 .69 0 0 0 .9 0h.6v.1a.7 .7 0 0 0 .8 .7 .7 .7 0 0 0 .6-.8h2.6v.1a.7 .7 0 0 0 .6 .7 .7 .7 0 0 0 .7-.5h4.8l.1 .4 .3 .3a.7 .7 0 0 0 .6 .8 .7 .7 0 0 0 .8-.6 .69 .69 0 0 0 .5-.9h.8v.1a.7 .7 0 0 0 1.1 .5 .7 .7 0 0 0 0-1.2 .7 .7 0 0 0-1.1 .6l-.8-.1a.69 .69 0 0 0-1-.3 .7 .7 0 0 0-.8-.2 .7 .7 0 0 0-.5 .6h-4.8l.1-.3a.77 .77 0 0 0 .1-.9l.1-1-.2-.4h4.7v.4l.4 .3a.7 .7 0 0 0-.2 .9 .7 .7 0 0 0 .9 .3h6.6v.2a.7 .7 0 0 0 1.1 .5 .7 .7 0 0 0 0-1.2 .7 .7 0 0 0-1.1 .5h-6.6l.3-.2 .1-.5 .2-.2h11.6v.2a.7 .7 0 0 0 1.1 .5 .7 .7 0 0 0 0-1.2 .7 .7 0 0 0-1.1 .5h-11.6h.1a.7 .7 0 0 0-.3-1h6.2v.1a.7 .7 0 0 0 1.1 .6 .7 .7 0 0 0 0-1.2 .7 .7 0 0 0-1.1 .5h-6.3a.72 .72 0 0 0-.8-.6 .72 .72 0 0 0-.6 .6h-4.7v-.1a.7 .7 0 0 0-.9 0 .7 .7 0 0 0-.2 .9l-.1 .5a.93 .93 0 0 1-.2 .9v.1h-2.6a.7 .7 0 0 0-.7-.6 .7 .7 0 0 0-.7 .6h-.6l.1-.1a.78 .78 0 0 0 .1-.8v-.7a.7 .7 0 0 0-.5-.9 .7 .7 0 0 0-.9 .6h-7l.1-.1a.7 .7 0 0 0-.7-.8 .7 .7 0 0 0-.7 .6h-12.1a.7 .7 0 0 0-.8-.2 .7 .7 0 0 0-.5 .6l-6.8-.1a.7 .7 0 0 0-.7-.8 .7 .7 0 0 0-.7 .7h-9.8v-.2a.7 .7 0 0 0-.8-.5 .7 .7 0 0 0-.6 .7h-36.5v-1.1h13.1v.2a.7 .7 0 0 0 .8 .6 .7 .7 0 0 0 .6-.8h7.3v.2a.7 .7 0 0 0 .7 .6 .7 .7 0 0 0 .7-.8h3.6v.2a.7 .7 0 0 0 .7 .6 .7 .7 0 0 0 .7-.6h23.3v.1a.7 .7 0 0 0 1.1 .5 .7 .7 0 0 0 0-1.1 .7 .7 0 0 0-1.1 .5h-23.3v-.2a.7 .7 0 0 0-.7-.6 .7 .7 0 0 0-.7 .6h-3.6l-.1-.1a.7 .7 0 0 0-.7-.5 .7 .7 0 0 0-.6 .6h-7.3v-.1a.7 .7 0 0 0-.7-.5 .7 .7 0 0 0-.7 .6h-13.1v-1.2h24.8v.1a.7 .7 0 0 0 .4 .6 .7 .7 0 0 0 .8-.2h53.6v.1a.7 .7 0 0 0 .5 .6 .7 .7 0 0 0 .8-.3h2.1v.1a.7 .7 0 0 0 1 .5 .7 .7 0 0 0 0-1.2 .7 .7 0 0 0-1 .6h-2.1v-.1a.7 .7 0 0 0-.5-.9 .7 .7 0 0 0-.8 .6h-53.6l.1-.1a.7 .7 0 0 0-.3-1l.3-.3h2.9a.7 .7 0 0 0 .7 .8 .7 .7 0 0 0 .7-.8h28.5v.2a.72 .72 0 0 0 .4 .6 .72 .72 0 0 0 .8-.2 .7 .7 0 0 0 .7 .1 .7 .7 0 0 0 .4-.7h12.1v.1a.7 .7 0 0 0 1.1 .6 .7 .7 0 0 0 0-1.2 .7 .7 0 0 0-1.1 .5h-12.1v-.1a.72 .72 0 0 0-1.2-.3 .7 .7 0 0 0-1.1 .4h-28.5a.7 .7 0 0 0-.7-.6 .7 .7 0 0 0-.7 .6h-2.9l.1-.4-.2-.4h5v.2a.7 .7 0 0 0 1.1 .5 .7 .7 0 0 0 0-1.2 .7 .7 0 0 0-1.1 .5h-5v-.1a.7 .7 0 0 0-1.1 .2 .7 .7 0 0 0 .3 1l-.3 .2-.1 .4h-24.8v-2.3h4.5v.1a.7 .7 0 0 0 1.1 .6 .7 .7 0 0 0 0-1.2 .7 .7 0 0 0-1.1 .5h-4.5v-2.2h13.1v.2a.7 .7 0 0 0 1.1 .5 .7 .7 0 0 0 0-1.2 .7 .7 0 0 0-1.1 .5h-13.1v-1.6h4.5v.1a.7 .7 0 0 0 1.1 .5h15.9l.1 .4 .3 .3a.7 .7 0 0 0 .2 1.2 .7 .7 0 0 0 .9-.7h1.3v.1a.7 .7 0 0 0 .6 .6 .7 .7 0 0 0 .7-.4h4.2v.2a.7 .7 0 0 0 .7 .6h3.6l.1 .4 .3 .3a.7 .7 0 0 0-.2 1.2 .7 .7 0 0 0 1.2-.4h1v.2a.7 .7 0 0 0 .8 .6 .7 .7 0 0 0 .6-.9h.6v.1a.7 .7 0 0 0 .9 .7 .7 .7 0 0 0 .5-.9h10.4v.1a.7 .7 0 0 0 .6 .6 .7 .7 0 0 0 .8-.5h4.2v.2a.7 .7 0 0 0 .9 .6 .7 .7 0 0 0 .5-1h.4v.2a.7 .7 0 0 0 1.1 .5 .7 .7 0 0 0 0-1.2 .7 .7 0 0 0-1.1 .5h-.5a.7 .7 0 0 0-.7-.4 .7 .7 0 0 0-.6 .6h-4.2v-.1a.7 .7 0 0 0-.7-.8 .7 .7 0 0 0-.7 .7h-10.4a.7 .7 0 0 0-.7-.5 .7 .7 0 0 0-.7 .6h-.6a.7 .7 0 0 0-.8-.5 .7 .7 0 0 0-.6 .6h-1l-.1-.5-.3-.3 .3-.3h17.6v.1a.7 .7 0 0 0 1 .6 .7 .7 0 0 0 .2-1.1h4.1v.1a.7 .7 0 0 0 .5 .6 .7 .7 0 0 0 .8-.2h.5v.1a.7 .7 0 0 0 .7 .7 .7 .7 0 0 0 .7-.7h2.6v.2a.7 .7 0 0 0 .6 .6 .7 .7 0 0 0 .7-.5h3.1v.1a.7 .7 0 0 0 .5 .6 .7 .7 0 0 0 .8-.3h9.2v.2a.69 .69 0 0 0 .5 .6 .69 .69 0 0 0 .7-.2h4.2v.1a.7 .7 0 0 0 1 .6 .7 .7 0 0 0 0-1.2 .7 .7 0 0 0-1 .5h-4.2l.2-.4v-.4a.69 .69 0 0 0 .4-.8h3.6v.1a.7 .7 0 0 0 .9 .6 .7 .7 0 0 0 .4-1h3.8v.1a.7 .7 0 0 0 .6 .7 .69 .69 0 0 0 .1 1.2 .7 .7 0 0 0-.1 1 .7 .7 0 0 0 1 .1h5.4v.1a.7 .7 0 0 0 1.1 .5 .7 .7 0 0 0 0-1.2 .7 .7 0 0 0-1.1 .6h-5.4l.2-.5-.1-.4h11.6a.7 .7 0 0 0 .8 .7 .7 .7 0 0 0 .5-.9h2.7v.1a.7 .7 0 0 0 1.1 .5 .7 .7 0 0 0 0-1.2 .7 .7 0 0 0-1.1 .6l-2.7-.1a.7 .7 0 0 0-.7-.4 .7 .7 0 0 0-.6 .7h-11.6l-.3-.3 .3-.2v-.4a.7 .7 0 0 0 .1-1.2 .73 .73 0 0 0 .4-.6 .7 .7 0 0 0 .6-.9h4.8l.1 .4a.79 .79 0 0 0 .3 1.1 .7 .7 0 0 0-.3 1 .7 .7 0 0 0 1.1 0 .7 .7 0 0 0-.2-1 .77 .77 0 0 0 .3-1.1v-.5h12.9v.1a.7 .7 0 0 0 1.1 .5 .7 .7 0 0 0 0-1.1 .7 .7 0 0 0-1.1 .5h-12.9a.7 .7 0 0 0-.7-.5 .7 .7 0 0 0-.6 .6h-4.8a.7 .7 0 0 0-.7-.5 .7 .7 0 0 0-.6 .6 .89 .89 0 0 0-.7 .7 .7 .7 0 0 0-.8 .6h-3.8a.7 .7 0 0 0-.8-.4 .7 .7 0 0 0-.5 .7h-3.6a.7 .7 0 0 0-.9-.5 .7 .7 0 0 0-.4 1l-.3 .2-.2 .3h-9.2a.7 .7 0 0 0-.4-1 .7 .7 0 0 0-.9 .6h-3.1v-.1a.7 .7 0 0 0-.6-.8 .7 .7 0 0 0-.7 .6h-2.6v-.1a.7 .7 0 0 0-.7-.6 .7 .7 0 0 0-.7 .6h-.5l.1-.1a.7 .7 0 0 0-.5-1 .7 .7 0 0 0-.9 .6h-4.1l-.1-.1a.7 .7 0 0 0-1.1 .5h-17.6l.1-.1a.7 .7 0 0 0-.6-.9 .7 .7 0 0 0-.8 .6h-3.6h.2a.7 .7 0 0 0 .2-1.2 .7 .7 0 0 0-1.1 .4h-4.2l.1-.1a.7 .7 0 0 0-.6-.9 .7 .7 0 0 0-.8 .7h-1.3l-.1-.4-.3-.2 .3-.3-.1-.5h1.6v.1a.7 .7 0 0 0 .5 .6 .7 .7 0 0 0 .8-.2h14.1v.1a.7 .7 0 0 0 1.1 .5 .7 .7 0 0 0 0-1.2 .7 .7 0 0 0-1.1 .6h-14.1l.1-.4-.1-.4 .5-.2h3.2a.7 .7 0 0 0 .7 .7 .7 .7 0 0 0 .7-.7h37.1v.1a.7 .7 0 0 0 .9 .6 .7 .7 0 0 0 .4-1h4.1v.1a.7 .7 0 0 0 1.1 .6 .7 .7 0 0 0 0-1.2 .7 .7 0 0 0-1.1 .5h-4.1a.7 .7 0 0 0-.8-.4 .7 .7 0 0 0-.5 .7h-37.1v-.2a.7 .7 0 0 0-.8-.5 .7 .7 0 0 0-.6 .7h-3.2l.1-.2a.7 .7 0 0 0-.7-1 .7 .7 0 0 0-.6 1l-.4 .3-.2 .4h-1.6a.7 .7 0 0 0-.7-.4 .7 .7 0 0 0-.6 .6h-15.9l.3-.3-.1-.6h2.1a.7 .7 0 0 0 1 .8 .7 .7 0 0 0 .2-1.2 .7 .7 0 0 0-1.1 .3l-.1 .1h-2.1a.7 .7 0 0 0-.7-.3 .7 .7 0 0 0-.6 .6h-4.5v-.9h9.7v.1a.7 .7 0 0 0 1.1 .6 .7 .7 0 0 0 0-1.2 .7 .7 0 0 0-1.1 .5h-9.7v-1.3h16.2v.2a.7 .7 0 0 0 .9 .6 .7 .7 0 0 0 .4-1.1h4v.1a.69 .69 0 0 0 .7 .7 .7 .7 0 0 0-.2 1.1 .7 .7 0 0 0 1.1-.2 .7 .7 0 0 0-.6-1l.3-.2h1.8v.1a.7 .7 0 0 0 .8 .6 .7 .7 0 0 0 .6-.8h1.1v.2a.7 .7 0 0 0 1.1 .5h4.6v.1a.7 .7 0 0 0 .8 .6 .7 .7 0 0 0 .6-.8h2.4v.1a.7 .7 0 0 0 .7 .6 .7 .7 0 0 0 .7-.5h8.7v.1a.7 .7 0 0 0 .8 .7 .7 .7 0 0 0 .6-.8h3.5v.1a.7 .7 0 0 0 1.1 .6 .7 .7 0 0 0 0-1.2 .7 .7 0 0 0-1.1 .5h-3.5v-.1a.7 .7 0 0 0-.7-.5 .7 .7 0 0 0-.7 .6h-8.7v-.4l-.1-.2h18a.7 .7 0 0 0 .4 .6 .7 .7 0 0 0 .7 0h4.1v.1a.7 .7 0 0 0 1.1 .6 .7 .7 0 0 0 0-1.2 .7 .7 0 0 0-1.1 .5h-4a.69 .69 0 0 0-.1-1.1h5.5v.1a.7 .7 0 0 0 .9 .6 .7 .7 0 0 0 .5-.9h74.3v.2a.7 .7 0 0 0 1.1 .5 .7 .7 0 0 0 0-1.2 .7 .7 0 0 0-1.1 .5h-74.3a.7 .7 0 0 0-.7-.5 .7 .7 0 0 0-.7 .7l-5.5-.1a.7 .7 0 0 0-1.1 .6h-18l-.1-.1a.7 .7 0 0 0-1.2 .5h-2.4a.7 .7 0 0 0-.8-.5 .7 .7 0 0 0-.6 .6h-4.6l.3-.4-.1-.5h3.3a.7 .7 0 0 0 .9 .7 .7 .7 0 0 0 .2-1.1 .7 .7 0 0 0-1.1 .3v.1h-3.3a.7 .7 0 0 0-.7-.4 .7 .7 0 0 0-.6 .6h-1.1v-.1a.7 .7 0 0 0-.7-.5 .7 .7 0 0 0-.7 .7l-1.8-.1a.7 .7 0 0 0-.4-1 .7 .7 0 0 0-.9 .6l-4.1-.1a.7 .7 0 0 0-.7-.2 .7 .7 0 0 0-.5 .6h-16.2v-2.5h14.9v.1a.7 .7 0 0 0 1.1 .5 .7 .7 0 0 0 0-1.1 .7 .7 0 0 0-1.1 .5h-14.9v-1.3h19.9l.1 .5 .4 .3a.71 .71 0 0 0 .5 .8 .71 .71 0 0 0 .9-.6h6.1v.2a.7 .7 0 0 0 .9 .6 .7 .7 0 0 0 .5-.9h17.6v.1a.7 .7 0 0 0 1 .6 .7 .7 0 0 0 .2-1.1h1.1v.1a.7 .7 0 0 0 .5 .6 .7 .7 0 0 0 .8-.3h1.5v.1a.7 .7 0 0 0 .8 .7 .7 .7 0 0 0 .6-.9h2.4v.1a.7 .7 0 0 0 .7 .6 .7 .7 0 0 0 .7-.7h.4v.2a.7 .7 0 0 0 .8 .6 .7 .7 0 0 0 .6-.8h.6v.1a.7 .7 0 0 0 .7 .6 .7 .7 0 0 0 .7-.7h.4v.2a.7 .7 0 0 0 .6 .6 .7 .7 0 0 0 .7-.5 .7 .7 0 0 0 .8 .6 .7 .7 0 0 0 .6-.8h2.2v.1a.7 .7 0 0 0 .8 .7 .7 .7 0 0 0 .6-.7h39.5v.2a.95 .95 0 0 0 1.5 .7 .95 .95 0 0 0 0-1.6 .95 .95 0 0 0-1.5 .7h-39.5v-.1a.7 .7 0 0 0-.7-.6 .7 .7 0 0 0-.7 .6h-2.2v-.1a.7 .7 0 0 0-.7-.5 .7 .7 0 0 0-.6 .4 .7 .7 0 0 0-.8-.5 .7 .7 0 0 0-.6 .6h-.4a.7 .7 0 0 0-.7-.7 .7 .7 0 0 0-.7 .7l-.7-.1a.7 .7 0 0 0-.7-.5 .7 .7 0 0 0-.6 .6h-.4a.7 .7 0 0 0-.7-.7 .7 .7 0 0 0-.7 .7h-2.4a.7 .7 0 0 0-.8-.5 .7 .7 0 0 0-.6 .6h-1.5a.7 .7 0 0 0-.4-1 .7 .7 0 0 0-.9 .6l-1.1-.1a.7 .7 0 0 0-1.2 .5h-17.6a.7 .7 0 0 0-.7-.5 .7 .7 0 0 0-.7 .6h-6.1a.69 .69 0 0 0-.6-.8v-.4h7.8v.1a.7 .7 0 0 0 .9 .6 .7 .7 0 0 0 .4-.9h20.2v.1a.7 .7 0 0 0 .8 .6 .7 .7 0 0 0 .5-.8h82.7l.1 1.1-.1 .2 .1 .5-.1 .7a.7 .7 0 0 0 .7 .9 .7 .7 0 0 0 .6-1v-2.1a.7 .7 0 0 0-.5-.9 .7 .7 0 0 0-.8 .6h-82.7v-.1a.7 .7 0 0 0-.7-.5 .7 .7 0 0 0-.6 .7h-20.2v-.1a.7 .7 0 0 0-.7-.4 .7 .7 0 0 0-.6 .7h-7.8a.7 .7 0 0 0-.8-.4 .7 .7 0 0 0-.5 .6h-19.9v-1.9h5.4v.1a.88 .88 0 0 0 .6 .7 .7 .7 0 0 0 .9 .6 .7 .7 0 0 0 .5-.9h1.8v.1a.7 .7 0 0 0 .8 .6 .7 .7 0 0 0 .6-.7h7.4v.1a.7 .7 0 0 0 1 .5 .7 .7 0 0 0 0-1.2 .7 .7 0 0 0-1 .6h-7.4l-.2-.5h.1a.69 .69 0 0 0 .5-.6 .69 .69 0 0 0-.3-.7h17.4v.2a.7 .7 0 0 0 .6 .6 .7 .7 0 0 0 .7-.4h2.7v.4l.4 .3a.7 .7 0 0 0-.3 1.1 .7 .7 0 0 0 1.1 0 .7 .7 0 0 0-.3-1.1 .69 .69 0 0 0 .4-.8h28.2v.1a.7 .7 0 0 0 1 .6 .7 .7 0 0 0 .1-1.2h49.4v.1a.7 .7 0 0 0 1 .5 .7 .7 0 0 0 0-1.1 .7 .7 0 0 0-1 .5l-49.5-.1a.7 .7 0 0 0-1 .6h-28.2a.7 .7 0 0 0-.7-.5 .7 .7 0 0 0-.6 .6h-2.7l.1-.1a.7 .7 0 0 0-.5-.9 .7 .7 0 0 0-.9 .6h-17.5a.7 .7 0 0 0-.9 .2 .7 .7 0 0 0 .1 .9l-.4 .3-.2 .4h-1.8l-.4-.4a.4 .4 0 0 1-.2-.7 .7 .7 0 0 0-.9-.7 .7 .7 0 0 0-.4 1l-.1 .3h-5.4v-2.3h13.5v.2a.7 .7 0 0 0 .9 .6 .7 .7 0 0 0 .4-1h7.4v.1a.7 .7 0 0 0 .6 .6 .7 .7 0 0 0 .7-.5h29.1v.2a.7 .7 0 0 0 .8 .6 .7 .7 0 0 0 .6-.8h1v.2a.7 .7 0 0 0 1.1 .5 .7 .7 0 0 0 0-1.2 .7 .7 0 0 0-1.1 .5h-1v-.1a.7 .7 0 0 0-.7-.5 .7 .7 0 0 0-.7 .6h-29.1v-.1a.7 .7 0 0 0-.6-.8 .7 .7 0 0 0-.7 .7h-7.4a.7 .7 0 0 0-.7-.4 .7 .7 0 0 0-.6 .6h-13.5v-1.4h14.4v.2a.7 .7 0 0 0 .5 .6 .7 .7 0 0 0 .8-.3h31.2v.1a.7 .7 0 0 0 .7 .6 .7 .7 0 0 0 .7-.7h10.7v.2a.69 .69 0 0 0 1.1 .5h22v.1a.7 .7 0 0 0 1.1 .5 .7 .7 0 0 0-.1-1.2h20.3v.2a.95 .95 0 0 0 1.5 .7 .95 .95 0 0 0 0-1.6 .95 .95 0 0 0-1.5 .7h-20.3a.7 .7 0 0 0-1 .6l-22-.1a.7 .7 0 0 0-.1-1.1 .7 .7 0 0 0-1 .5h-10.7a.7 .7 0 0 0-.7-.7 .7 .7 0 0 0-.7 .7h-31.2l.1-.5-.3-.4h85.4a.95 .95 0 0 0 1.1 1 .95 .95 0 0 0 .7-1.3h5.3v.1a.7 .7 0 0 0 .8 .6 .7 .7 0 0 0 .6-.9h.9v.2a.94 .94 0 0 0 1.5 .7h16v2a.57 .57 0 0 0 .6 .6h2l.3-.1 .3-.4v-1.3h1.9v.3a1.58 1.58 0 0 0 1.7 1.5 1.58 1.58 0 0 0 1.4-1.8h2v.3a1.58 1.58 0 0 0 1.7 1.5 1.58 1.58 0 0 0 1.4-1.8h2v.3a1.58 1.58 0 0 0 2.4 1.2 1.58 1.58 0 0 0 0-2.7 1.58 1.58 0 0 0-2.4 1.2h-2v-.3a1.58 1.58 0 0 0-1.7-1.1 1.58 1.58 0 0 0-1.4 1.4h-2v-.3a1.58 1.58 0 0 0-1.7-1.1 1.58 1.58 0 0 0-1.4 1.4h-1.9v-.8a.57 .57 0 0 0-.6-.6h-2.1l-.3 .2-.2 .4h-16a.95 .95 0 0 0-.1-1.6 .95 .95 0 0 0-1.4 .7h-.9l-.1-.1a.7 .7 0 0 0-.7-.4 .7 .7 0 0 0-.6 .7l-5.3-.1a.95 .95 0 0 0-1-.5 .95 .95 0 0 0-.8 .9h-85.4a.7 .7 0 0 0-1.1 .4h-14.4v-1.9h7.8v.2a.7 .7 0 0 0 1.1 .5 .7 .7 0 0 0 0-1.2 .7 .7 0 0 0-1.1 .5h-7.8v-1.4h14.5v.2a.8 .8 0 0 0 .8 .6 .7 .7 0 0 0-.3 1.2 .7 .7 0 0 0 1.2-.3h1.6v.1a.7 .7 0 0 0 .8 .6 .7 .7 0 0 0 .6-.7h9.9v.1a.7 .7 0 0 0 .9 .6 .7 .7 0 0 0 .4-1h16.5v.2a.7 .7 0 0 0 .8 .6 .7 .7 0 0 0 .6-.8h.8v.2a.7 .7 0 0 0 .8 .6 .7 .7 0 0 0 .5-.9h.3v.1a.7 .7 0 0 0 .6 .6 .7 .7 0 0 0 .7-.3 .7 .7 0 0 0 .8 .5 .7 .7 0 0 0 .6-.8h.8v.2a.7 .7 0 0 0 .8 .6 .7 .7 0 0 0 .5-.9h.3v.1a.7 .7 0 0 0 .7 .7 .7 .7 0 0 0 .7-.7h.5v.2a.7 .7 0 0 0 .8 .6 .7 .7 0 0 0 .6-.8h.6v.2a.7 .7 0 0 0 .9 .6 .7 .7 0 0 0 .5-.9h.3v.1a.7 .7 0 0 0 .5 .6 .7 .7 0 0 0 .8-.3 .7 .7 0 0 0 .8 .5 .7 .7 0 0 0 .6-.8h.8v.2a.7 .7 0 0 0 .8 .6 .7 .7 0 0 0 .6-.8h.3v.2a.7 .7 0 0 0 1.1 .5 .7 .7 0 0 0 0-1.2 .7 .7 0 0 0-1.1 .5h-.3v-.1a.7 .7 0 0 0-.7-.5 .7 .7 0 0 0-.7 .6h-.8l-.1-.1a.7 .7 0 0 0-.6-.5 .7 .7 0 0 0-.6 .3 .7 .7 0 0 0-.8-.4 .7 .7 0 0 0-.6 .6h-.3a.7 .7 0 0 0-.7-.5 .7 .7 0 0 0-.7 .6h-.6v-.1a.7 .7 0 0 0-.8-.5 .7 .7 0 0 0-.6 .6h-.5v-.1a.7 .7 0 0 0-.7-.6 .7 .7 0 0 0-.7 .6h-.3a.7 .7 0 0 0-.7-.5 .7 .7 0 0 0-.6 .6h-.8v-.1a.7 .7 0 0 0-.6-.5 .7 .7 0 0 0-.7 .3 .7 .7 0 0 0-.8-.4 .7 .7 0 0 0-.6 .6h-.3a.7 .7 0 0 0-.7-.5 .7 .7 0 0 0-.6 .6h-.8v-.1a.7 .7 0 0 0-.8-.5 .7 .7 0 0 0-.6 .6h-16.5a.7 .7 0 0 0-.7-.3 .7 .7 0 0 0-.6 .6h-9.9v-.2a.7 .7 0 0 0-.7-.5 .7 .7 0 0 0-.7 .7h-1.6l-.1-.6a.69 .69 0 0 0 .5-.5 .69 .69 0 0 0-.4-.7h2.1v.1a.7 .7 0 0 0 .5 .6 .7 .7 0 0 0 .8-.2h7.5v.1a.7 .7 0 0 0 .8 .7 .7 .7 0 0 0 .6-.8h3.4v.1a.7 .7 0 0 0 1.1 .6 .7 .7 0 0 0 0-1.2 .7 .7 0 0 0-1.1 .5h-3.4v-.1a.7 .7 0 0 0-.8-.5 .7 .7 0 0 0-.6 .6h-7.5l.1-.1a.7 .7 0 0 0-.5-1 .7 .7 0 0 0-.9 .6h-2.1l-.4-.1a.7 .7 0 0 0-.7-.4 .7 .7 0 0 0-.6 .6h-14.5v-1h6v.1a.7 .7 0 0 0 1.1 .6 .7 .7 0 0 0 0-1.2 .7 .7 0 0 0-1.1 .5h-6v-1h14.9v.1a.7 .7 0 0 0 .8 .7 .7 .7 0 0 0 .6-.8h3.6v.1a.7 .7 0 0 0 .7 .7h61.5v.1a.7 .7 0 0 0 1 .5h2.4v.2a.95 .95 0 0 0 1 .9 .95 .95 0 0 0 .9-.9 .95 .95 0 0 0-.8-1h16.8v.2a.95 .95 0 0 0 1.4 .8 .95 .95 0 0 0 .3-1.5h22.7v2a.57 .57 0 0 0 .6 .6h2l.3-.1 .3-.4v-1.3h1.9v.3a1.58 1.58 0 0 0 1.7 1.4 1.58 1.58 0 0 0 1.4-1.7h2v.3a1.58 1.58 0 0 0 1.7 1.4 1.58 1.58 0 0 0 1.4-1.7h2v.3a1.58 1.58 0 0 0 2.4 1.2 1.58 1.58 0 0 0 0-2.7 1.58 1.58 0 0 0-2.4 1.2h-2v-.3a1.58 1.58 0 0 0-1.7-1.1 1.58 1.58 0 0 0-1.4 1.4h-2v-.3a1.58 1.58 0 0 0-1.7-1.1 1.58 1.58 0 0 0-1.4 1.4h-1.9v-.8a.57 .57 0 0 0-.6-.6h-2.1l-.3 .2-.2 .4h-22.7a.95 .95 0 0 0-1-.3 .95 .95 0 0 0-.7 .8h-16.8a.95 .95 0 0 0-1.1 .8h-2.4a.7 .7 0 0 0 .1-1.2 .7 .7 0 0 0-1.1 .6h-61.5l.2-.1a.7 .7 0 0 0 .4-1h9.3v.2a.7 .7 0 0 0 1.1 .5 .7 .7 0 0 0 0-1.2 .7 .7 0 0 0-1.1 .5h-9.3a.7 .7 0 0 0-.8-.3 .7 .7 0 0 0-.5 .6h-3.6v-.1a.7 .7 0 0 0-.8-.5 .7 .7 0 0 0-.6 .6h-14.9v-1.2h5.1v.2a.7 .7 0 0 0 1 .6 .7 .7 0 0 0 .3-1.1h2.5v.1a.7 .7 0 0 0 .7 .6 .7 .7 0 0 0 .7-.5h2.7v.2a.7 .7 0 0 0 1.1 .5 .7 .7 0 0 0 0-1.2 .7 .7 0 0 0-1.1 .5h-2.7v-.1a.7 .7 0 0 0-.6-.8 .7 .7 0 0 0-.8 .7h-2.5l-.1-.1a.7 .7 0 0 0-1.2 .4h-5.1v-1.3h15v.1a.69 .69 0 0 0 .8 .6h8.3v.1a.7 .7 0 0 0 1 .6 .7 .7 0 0 0 0-1.2h5.6v.1a.7 .7 0 0 0 .5 .6 .7 .7 0 0 0 .7-.2h2.8v.2a.7 .7 0 0 0 .9 .6h74.4v.1a.95 .95 0 0 0 1.5 .8 .95 .95 0 0 0 0-1.7 .95 .95 0 0 0-1.5 .8h-74.4a.7 .7 0 0 0 .3-1.3 .7 .7 0 0 0-1.2 .5h-2.8l.1-.1a.7 .7 0 0 0-.4-1 .7 .7 0 0 0-.9 .6h-5.6a.7 .7 0 0 0-1 .5h-8.3h.1a.7 .7 0 0 0 .3-1.2 .7 .7 0 0 0-1.2 .5h-15v-.9h20.6v.1a.7 .7 0 0 0 .9 .6 .7 .7 0 0 0 .4-1h4.4v.1a.7 .7 0 0 0 1.1 .6 .7 .7 0 0 0 0-1.2 .7 .7 0 0 0-1.1 .5h-4.4a.7 .7 0 0 0-.7-.4 .7 .7 0 0 0-.6 .7h-20.6v-2.3h13.4v.1a.7 .7 0 0 0 .6 .6 .7 .7 0 0 0 .7-.3h3.9v.1a.7 .7 0 0 0 .5 .6 .7 .7 0 0 0 .7-.2h4.9v.1a.7 .7 0 0 0 .8 .6 .7 .7 0 0 0 .6-.7h2.9v.1a.7 .7 0 0 0 .7 .6 .7 .7 0 0 0 .7-.5h5.7l.1 .6 .6 .5a1.14 1.14 0 0 0 .3 1.3 1.14 1.14 0 0 0 1.2 .2 1.14 1.14 0 0 0 1.4 .7 1.14 1.14 0 0 0 .8-1.3h6.4v.1a.69 .69 0 0 0 .9 .6h10.4v.1a.7 .7 0 0 0 1.1 .5 .7 .7 0 0 0 0-1.1 .7 .7 0 0 0-1.1 .5h-10.4l.4-.3v-.4h15.7v.2a.95 .95 0 0 0 1.4 .8 .95 .95 0 0 0 .2-1.6h8.7v.2a.95 .95 0 0 0 1.5 .7 .95 .95 0 0 0 0-1.6 .95 .95 0 0 0-1.5 .7h-8.7a.95 .95 0 0 0-1.6 .6h-15.7a.7 .7 0 0 0-.7-.6 .7 .7 0 0 0-.6 .6h-6.4v-.1a1.14 1.14 0 0 0-1.6-.8l-.1-.3-.5-.3 .1-.1a1.15 1.15 0 0 0-.9-1.4 1.15 1.15 0 0 0-1.4 1h-5.7v-.1a.7 .7 0 0 0-.6-.8 .7 .7 0 0 0-.8 .7h-2.9v-.2a.7 .7 0 0 0-.8-.5 .7 .7 0 0 0-.6 .7h-4.9l.1-.1a.7 .7 0 0 0-.4-1 .7 .7 0 0 0-.9 .6h-3.9v-.2a.7 .7 0 0 0-.5-.8 .7 .7 0 0 0-.8 .6h-13.4v-2.2h16.2v.2a.7 .7 0 0 0 .7 .6h2.7v.1a.7 .7 0 0 0 .9 .6 .7 .7 0 0 0 .4-1h6.2v.2a.7 .7 0 0 0 .7 .6 .7 .7 0 0 0 .7-.8h3.6v.2a.69 .69 0 0 0 1 .5h5.1v.2a1.14 1.14 0 0 0 1.6 .9l.3 .5 .3 .2v.1a1.15 1.15 0 0 0 1.2 1.4 1.15 1.15 0 0 0 .8-1.7h4.4v.1a.7 .7 0 0 0 .8 .7 .7 .7 0 0 0 .6-.8h2.5v.1a.7 .7 0 0 0 .7 .7 .7 .7 0 0 0 .7-.5 .7 .7 0 0 0 .8 .5 .7 .7 0 0 0 .5-.8h.6v.1a.7 .7 0 0 0 .8 .7 .7 .7 0 0 0 .6-.8h.4v.1a.7 .7 0 0 0 .8 .7 .7 .7 0 0 0 .6-.8h70.6v2a.57 .57 0 0 0 .6 .5h2l.3-.1 .3-.3v-1.3h1.9v.3a1.58 1.58 0 0 0 1.7 1.4 1.58 1.58 0 0 0 1.4-1.7h2v.3a1.58 1.58 0 0 0 1.7 1.4 1.58 1.58 0 0 0 1.4-1.7h2v.3a1.58 1.58 0 0 0 2.4 1.2 1.58 1.58 0 0 0 0-2.7 1.58 1.58 0 0 0-2.4 1.2h-2v-.3a1.58 1.58 0 0 0-1.7-1.1 1.58 1.58 0 0 0-1.4 1.4h-2v-.3a1.58 1.58 0 0 0-1.7-1.1 1.58 1.58 0 0 0-1.4 1.4h-1.9v-.8a.57 .57 0 0 0-.6-.6h-2.1l-.3 .2-.2 .4h-70.6a.7 .7 0 0 0-.7-.6 .7 .7 0 0 0-.7 .6h-.4v-.1a.7 .7 0 0 0-.7-.5 .7 .7 0 0 0-.7 .6h-.6v-.1a.7 .7 0 0 0-.6-.5 .7 .7 0 0 0-.7 .5 .7 .7 0 0 0-.7-.5 .7 .7 0 0 0-.7 .6h-2.5v-.1a.7 .7 0 0 0-.8-.5 .7 .7 0 0 0-.6 .6h-4.4l-.5-.5 .1-.6h7.6a.7 .7 0 0 0 .9 .7 .7 .7 0 0 0 .3-1.2 .7 .7 0 0 0-1.2 .3v.2h-7.6a1.13 1.13 0 0 0-1.6-.9 1.15 1.15 0 0 0-1.2-.6 1.15 1.15 0 0 0-1 1h-5.1l.1-.1a.7 .7 0 0 0-.1-1.1 .7 .7 0 0 0-1 .5h-3.6l-.1-.1a.7 .7 0 0 0-.7-.5 .7 .7 0 0 0-.6 .6h-6.2a.7 .7 0 0 0-.7-.3 .7 .7 0 0 0-.6 .6h-2.7h.2a.7 .7 0 0 0 .2-1.3 .7 .7 0 0 0-1.1 .5h-16.2v-1.7h3.2v.2a1.05 1.05 0 0 0 1.1 1 1.05 1.05 0 0 0 1-1.2h.4v.2a1.05 1.05 0 0 0 1.2 1 1.05 1.05 0 0 0 .9-1.2h.5v.2a1.05 1.05 0 0 0 1.4 .9 1.05 1.05 0 0 0 .5-1.6h.6v1.2a.45 .45 0 0 0 .5 .5h1.2l.3-.1 .1-.3h81a.95 .95 0 0 0 1.3 1 .95 .95 0 0 0 .3-1.6 .95 .95 0 0 0-1.6 .4v.2h-81v-1.1h2v.1a.7 .7 0 0 0 .8 .6 .7 .7 0 0 0 .6-.7h6.4v.1a.7 .7 0 0 0 .7 .7 .7 .7 0 0 0 .6-.7h.6v.1a.7 .7 0 0 0 1 .6 .7 .7 0 0 0 0-1.2 .7 .7 0 0 0-1 .5h-.6v-.1a.7 .7 0 0 0-.6-.6 .7 .7 0 0 0-.7 .6h-6.4v-.1a.7 .7 0 0 0-.8-.5 .7 .7 0 0 0-.6 .6h-2v-.2a.45 .45 0 0 0-.4-.4h-1.3l-.3 .1-.1 .3h-.6a1.05 1.05 0 0 0-1.1-.4 1.05 1.05 0 0 0-.8 .9h-.5v-.2a1.05 1.05 0 0 0-1.1-.7 1.05 1.05 0 0 0-1 .9h-.4l-.1-.2a1.05 1.05 0 0 0-1.1-.7 1.05 1.05 0 0 0-.9 .9h-3.2v-1.8h7.9v.1a.7 .7 0 0 0 .7 .6 .7 .7 0 0 0 .7-.5h10.6v.2a.69 .69 0 0 0 1.1 .5h8v.1a.7 .7 0 0 0 .8 .6 .7 .7 0 0 0 .6-.7h7.1v.1a.7 .7 0 0 0 .5 .6 .7 .7 0 0 0 .8-.2h2.7v.1a.7 .7 0 0 0 .6 .6 .7 .7 0 0 0 .7-.5h64.6v.2a.95 .95 0 0 0 1 .8 .95 .95 0 0 0 .8-1.1h5.5v.2a.95 .95 0 0 0 .9 .9 .95 .95 0 0 0 1-.7h16.3v.3a1.58 1.58 0 0 0 1.7 1.4 1.58 1.58 0 0 0 1.4-1.7h2v.3a1.58 1.58 0 0 0 1.7 1.4 1.58 1.58 0 0 0 1.4-1.7h2v.3a1.58 1.58 0 0 0 2.4 1.2 1.58 1.58 0 0 0 0-2.7 1.58 1.58 0 0 0-2.4 1.2h-2v-.3a1.58 1.58 0 0 0-1.7-1.1 1.58 1.58 0 0 0-1.4 1.4h-2v-.3a1.58 1.58 0 0 0-1.7-1.1 1.58 1.58 0 0 0-1.4 1.4h-16.3a.95 .95 0 0 0-.7-1.2 .95 .95 0 0 0-1.2 .8h-5.5v-.1a.95 .95 0 0 0-1-.7 .95 .95 0 0 0-.8 .9h-64.6v-.1a.7 .7 0 0 0-.6-.8 .7 .7 0 0 0-.7 .7h-2.7l.1-.4-.1-.5h55.1v.2a.95 .95 0 0 0 1.4 .8 .95 .95 0 0 0 .2-1.6h14.7v.2a1.2 1.2 0 0 0 1.3 1.1 1.2 1.2 0 0 0 1.1-1.3h11.9v.3a1.33 1.33 0 0 0 2 1 1.33 1.33 0 0 0 0-2.3 1.33 1.33 0 0 0-2 1h-11.9l-.1-.2a1.2 1.2 0 0 0-1.3-.9 1.2 1.2 0 0 0-1 1.1h-14.7a.95 .95 0 0 0-1.6 .6h-55.1a.7 .7 0 0 0-.8-.2 .7 .7 0 0 0-.5 .6h-7.1v-.2a.7 .7 0 0 0-.8-.5 .7 .7 0 0 0-.6 .7l-8-.1a.7 .7 0 0 0-.1-1.1 .7 .7 0 0 0-1 .5h-10.6v-.4l-.1-.2h33.4a.7 .7 0 0 0 .9 .7 .7 .7 0 0 0 .3-1.2 .7 .7 0 0 0-1.2 .3v.2h-33.4a.7 .7 0 0 0-.8-.2 .7 .7 0 0 0-.5 .6h-7.9v-2.8h4.2v.1a.7 .7 0 0 0 .5 .6 .7 .7 0 0 0 .8-.2h7.5v.1a.7 .7 0 0 0 .8 .6 .7 .7 0 0 0 .6-.7h3.4v.1a.7 .7 0 0 0 .8 .6h1.8v.2a.7 .7 0 0 0 .8 .6 .7 .7 0 0 0 .5-.9h10.2v.1a.7 .7 0 0 0 .8 .7 .7 .7 0 0 0 .6-.8h7.3v.1a.7 .7 0 0 0 1 .6 .7 .7 0 0 0 0-1.2 .7 .7 0 0 0-1 .5h-7.3v-.1a.7 .7 0 0 0-.7-.5 .7 .7 0 0 0-.7 .6h-10.2a.7 .7 0 0 0-.7-.5 .7 .7 0 0 0-.6 .6h-1.8h.1a.7 .7 0 0 0 .5-.9h67.1v.2a.95 .95 0 0 0 1.4 .7 .95 .95 0 0 0 0-1.6 .95 .95 0 0 0-1.4 .7h-67.1l-.1-.1a.7 .7 0 0 0-.7-.3 .7 .7 0 0 0-.6 .6h-3.4v-.2a.7 .7 0 0 0-.8-.5 .7 .7 0 0 0-.6 .7h-7.5l.1-.1a.7 .7 0 0 0-.5-1 .7 .7 0 0 0-.9 .6h-4.2v-1.3h127.8v2a.57 .57 0 0 0 .6 .5h2l.3-.1 .3-.3v-1.3h1.9v.3a1.58 1.58 0 0 0 1.7 1.4 1.58 1.58 0 0 0 1.4-1.7h2v.3a1.58 1.58 0 0 0 1.7 1.4 1.58 1.58 0 0 0 1.4-1.7h2v.3a1.58 1.58 0 0 0 2.4 1.2 1.58 1.58 0 0 0 0-2.7 1.58 1.58 0 0 0-2.4 1.2h-2v-.3a1.58 1.58 0 0 0-1.7-1.1 1.58 1.58 0 0 0-1.4 1.4h-2v-.3a1.58 1.58 0 0 0-1.7-1.1 1.58 1.58 0 0 0-1.4 1.4h-1.9v-.8a.57 .57 0 0 0-.6-.6h-2.1l-.3 .1-.2 .5h-127.8zM81.8 60.7h1.2v1.2h-1.2zM198.9 76.1h2v2h-2zM198.9 70.9h2v2h-2zM198.9 65.7h2v2h-2zM198.9 60.5h2v2h-2zM186.8 88.3v-.1h30l.1 .1v10.5l-.1 .1h-30v-.1v-1.1h15.2a.57 .57 0 0 0 .8 .6 .57 .57 0 0 0 .2-.9 .57 .57 0 0 0-1 .2v.1h-15.2v-1h1.9a.57 .57 0 0 0 .3 .6 .57 .57 0 0 0 .7-.2h5.1a.57 .57 0 0 0 .7 .6 .57 .57 0 0 0 .2-1 .57 .57 0 0 0-.9 .3v.1h-5.1a.57 .57 0 0 0-.3-.9 .57 .57 0 0 0-.7 .5h-1.9v-2.7h11.5a.57 .57 0 0 0 .8 .6 .57 .57 0 0 0 .2-.9 .57 .57 0 0 0-1 .2v.1h-11.5v-1.9h11.5a.57 .57 0 0 0 .5 .7 .57 .57 0 0 0 .6-.5 .57 .57 0 0 0-.4-.7h5.3a.57 .57 0 0 0 .8 .6 .57 .57 0 0 0 .1-.9 .57 .57 0 0 0-.9 .2v.1h-5.3a.57 .57 0 0 0-.7 .5h-11.5v-1.2h7.6a.57 .57 0 0 0 .7 .6 .57 .57 0 0 0 .2-1 .57 .57 0 0 0-.9 .3v.1h-7.6v-.7h11.5a.57 .57 0 0 0 .6 .7 .57 .57 0 0 0 .5-.8h10.9a.57 .57 0 0 0 .7 .6 .57 .57 0 0 0 .2-1 .57 .57 0 0 0-.9 .3v.1h-10.9a.57 .57 0 0 0-.6-.4 .57 .57 0 0 0-.5 .5h-11.5v-1.1h1.6a.57 .57 0 0 0 .8 .6 .57 .57 0 0 0 .2-1 .57 .57 0 0 0-1 .3v.1h-1.6zM188.4 118.4l.1-.1h18a1.07 1.07 0 0 0-.4 1.6l-.2 .5 .1 .4 .1 .4v.1a1.08 1.08 0 0 0 1 1.6 1.08 1.08 0 0 0 .8-1.7l.2-.6-.1-.6h4.3v.2a1.08 1.08 0 0 0 1.6 .9 1.08 1.08 0 0 0 0-1.9 1.08 1.08 0 0 0-1.6 .8h-4.3l-.1-.1 .1-.1a1.08 1.08 0 0 0-.5-1.5h11.1l-.2 .2a1.33 1.33 0 0 0 .7 2.1 1.33 1.33 0 0 0-1 1.2 1.33 1.33 0 0 0 1 1.3 1.33 1.33 0 0 0-.7 2.1 1.33 1.33 0 0 0 2.1 0 1.33 1.33 0 0 0-.7-2.1 1.33 1.33 0 0 0 1-1.3 1.33 1.33 0 0 0-1-1.2 1.33 1.33 0 0 0 .5-2.3h3.4l-.2 .2a1.33 1.33 0 0 0 .7 2.1 1.33 1.33 0 0 0-1 1.2 1.33 1.33 0 0 0 1 1.3 1.33 1.33 0 0 0-.7 2.1 1.33 1.33 0 0 0 2.1 0 1.33 1.33 0 0 0-.7-2.1 1.33 1.33 0 0 0 1-1.3 1.33 1.33 0 0 0-1-1.2 1.33 1.33 0 0 0 .5-2.3h3.8l.1 .1v22.8l-.3-.1a4.1 4.1 0 0 0-5.2 1.1 4.1 4.1 0 0 0 .4 5.4h-35.7l-.1-.1v-2.7h14.9a1.73 1.73 0 0 0 2.3 1.8 1.73 1.73 0 0 0 .6-2.9 1.73 1.73 0 0 0-2.8 .7l-.1 .4h-14.9v-3h6.4a1.68 1.68 0 0 0 1.9 1.8 1.68 1.68 0 0 0 1.3-2.2h13.1l.1 .3 .2 .4a.82 .82 0 0 0 0 1.3 .82 .82 0 0 0 0 1.2 .82 .82 0 0 0 0 1.3 .83 .83 0 0 0 0 1.2 .83 .83 0 0 0 1.2 0 .83 .83 0 0 0-.1-1.2 .82 .82 0 0 0 0-1.3 .82 .82 0 0 0 0-1.2 .82 .82 0 0 0 0-1.3l.3-.4v-.3h2.5l.1 .3 .2 .4-.1 .1a.82 .82 0 0 0 .1 1.2 .82 .82 0 0 0 0 1.2 .82 .82 0 0 0 0 1.3 .83 .83 0 0 0 0 1.2 .83 .83 0 0 0 1.2 0 .83 .83 0 0 0-.1-1.2 .82 .82 0 0 0 0-1.3 .82 .82 0 0 0 0-1.2 .82 .82 0 0 0 0-1.3 .83 .83 0 0 0-.2-1.4 .83 .83 0 0 0-1.2 .7h-2.5v-.2a.83 .83 0 0 0-.9-.5 .83 .83 0 0 0-.8 .7h-13.1v-.2a1.68 1.68 0 0 0-1.9-.9 1.68 1.68 0 0 0-1.3 1.5h-6.4v-7.6h6.4v.3a1.68 1.68 0 0 0 1.5 1.5 1.68 1.68 0 0 0 1.8-1.2h5.2v.3a1.73 1.73 0 0 0 1.9 1.6 1.73 1.73 0 0 0 1.5-1.9h1.1v.3a1.73 1.73 0 0 0 2.6 1.3 1.73 1.73 0 0 0 0-2.9 1.73 1.73 0 0 0-2.6 1.3h-1.1v-.4a1.73 1.73 0 0 0-1.9-1.2 1.73 1.73 0 0 0-1.5 1.6h-5.2v-.3a1.68 1.68 0 0 0-1.5-1.8 1.68 1.68 0 0 0-1.8 1.5h-6.4v-2.3h29.7l.2 .7 .3 .4 .5 .3a1.33 1.33 0 0 0-1 1.2 1.33 1.33 0 0 0 1 1.3 1.33 1.33 0 0 0-1 1.3 1.33 1.33 0 0 0 1 1.2 1.33 1.33 0 0 0-.7 2.1 1.33 1.33 0 0 0 2.1 0 1.33 1.33 0 0 0-.7-2.1 1.33 1.33 0 0 0 1-1.2 1.33 1.33 0 0 0-1-1.3 1.33 1.33 0 0 0 1-1.3 1.33 1.33 0 0 0-1-1.2l.5-.3 .3-.4 .2-.7h2.4l.2 .7 .3 .4 .5 .3-.3 .1a1.33 1.33 0 0 0-.7 1.3 1.33 1.33 0 0 0 1 1.1 1.33 1.33 0 0 0-1 1.3 1.33 1.33 0 0 0 1 1.2 1.33 1.33 0 0 0-.7 2.1 1.33 1.33 0 0 0 2.1 0 1.33 1.33 0 0 0-.7-2.1 1.33 1.33 0 0 0 1-1.2 1.33 1.33 0 0 0-1-1.3 1.33 1.33 0 0 0 1-1.3 1.33 1.33 0 0 0-1-1.2 1.33 1.33 0 0 0 .5-2.3 1.33 1.33 0 0 0-2.2 .9h-2.4l-.1-.3a1.33 1.33 0 0 0-1.4-.9 1.33 1.33 0 0 0-1.2 1.2h-29.7v-2.8h6.4v.3a1.68 1.68 0 0 0 2.6 1.3 1.68 1.68 0 0 0 0-2.8 1.68 1.68 0 0 0-2.6 1.2h-6.4zM195.1 100.6l.1-.1h21.6l.1 .1v2.1l.1 .2h12.2l.1 .1v7.2l-.1 .1h-2.2l-.1-.1v-4.8l-.2-.2h-12.4l-.1-.1v-2.7l-.2-.2h-17.4l-.2 .2v2.3a.57 .57 0 0 0-.5 .6 .57 .57 0 0 0 .5 .5v1.1l.2 .2h1.6l.1 .1v2.5l-.1 .1h-1.6l-.2 .2v1.1a.57 .57 0 0 0-.5 .5 .57 .57 0 0 0 .5 .6v2.3l.2 .2h16.6l.2-.1v-1.4l.1-.1h13.2l.2-.2v-2.1l.1-.1h2.2l.1 .1v4.5l-.1 .1h-12.6l-.1 .2v1h-.1h-21.2h-.1zM116.4 127.8h1.7v1.7h-1.7zM141.4 136.8h1v1h-1z"/>
<path d="M164.6 133.6h1.7v1.7h-1.7zM135.5 141.3h1.2v1.2h-1.2zM156.6 141.3h1.2v1.2h-1.2z"/>
<circle cx="72.1" cy="55" r=".25"/>
<circle cx="73.3" cy="53.8" r=".25"/>
<circle cx="75.4" cy="56.6" r=".25"/>
<circle cx="79.1" cy="59.4" r=".25"/>
<circle cx="79.1" cy="53.8" r=".25"/>
<circle cx="82" cy="56" r=".25"/>
<circle cx="84.1" cy="59.7" r=".25"/>
<circle cx="84.2" cy="57.1" r=".25"/>
<circle cx="85.1" cy="53.8" r=".25"/>
<circle cx="87.4" cy="57.1" r=".25"/>
<circle cx="89" cy="57.1" r=".25"/>
<circle cx="91.1" cy="59.7" r=".25"/>
<circle cx="91.1" cy="53.8" r=".25"/>
<circle cx="91.6" cy="57.9" r=".25"/>
<circle cx="97.1" cy="53.8" r=".25"/>
<circle cx="100.8" cy="57" r=".25"/>
<circle cx="103.1" cy="53.8" r=".25"/>
<circle cx="103.1" cy="57.8" r=".25"/>
<circle cx="106.7" cy="59" r=".25"/>
<circle cx="109.1" cy="53.8" r=".25"/>
<circle cx="110" cy="57.8" r=".25"/>
<circle cx="111.8" cy="57.8" r=".25"/>
<circle cx="113.8" cy="59" r=".25"/>
<circle cx="114.9" cy="53.8" r=".25"/>
<circle cx="116" cy="55" r=".25"/>
<circle cx="121.7" cy="55" r=".5"/>
<circle cx="157.7" cy="57" r=".5"/>
<circle cx="162.8" cy="56.9" r=".5"/>
<circle cx="178.8" cy="53.8" r=".5"/>
<circle cx="181.9" cy="59.4" r=".75"/>
<circle cx="196.3" cy="59.4" r=".75"/>
<circle cx="205" cy="56.3" r="1"/>
<circle cx="210.1" cy="56.3" r="1"/>
<circle cx="215.1" cy="56.3" r="1"/>
<circle cx="227.1" cy="55.8" r="2.05"/>
<circle cx="72" cy="66.8" r=".25"/>
<circle cx="72" cy="78.8" r=".25"/>
<circle cx="72" cy="72.8" r=".25"/>
<circle cx="72.1" cy="60.8" r=".25"/>
<circle cx="74.7" cy="61.3" r=".6"/>
<circle cx="75.9" cy="60.2" r=".25"/>
<circle cx="76.3" cy="69.7" r=".25"/>
<circle cx="76.5" cy="64.6" r=".25"/>
<circle cx="76.6" cy="79.8" r=".25"/>
<circle cx="76.6" cy="79.2" r=".25"/>
<circle cx="77.2" cy="71.9" r=".25"/>
<circle cx="77.3" cy="61.3" r=".6"/>
<circle cx="78.4" cy="69.3" r=".25"/>
<circle cx="79" cy="74.3" r=".25"/>
<circle cx="79.1" cy="71.9" r=".25"/>
<circle cx="79.8" cy="65" r=".25"/>
<circle cx="79.8" cy="61.3" r=".6"/>
<circle cx="80.1" cy="69.3" r=".25"/>
<circle cx="80.8" cy="79.1" r=".25"/>
<circle cx="81.3" cy="77.1" r=".25"/>
<circle cx="84.2" cy="69.6" r=".25"/>
<circle cx="84.6" cy="65.1" r=".25"/>
<circle cx="84.7" cy="77.6" r=".25"/>
<circle cx="85.6" cy="76.2" r=".25"/>
<circle cx="85.7" cy="72.9" r=".25"/>
<circle cx="86" cy="74.3" r=".25"/>
<circle cx="86.1" cy="61" r=".25"/>
<circle cx="86.1" cy="70.9" r=".25"/>
<circle cx="86.2" cy="68.3" r=".25"/>
<circle cx="86.4" cy="73.3" r=".25"/>
<circle cx="87" cy="77" r=".25"/>
<circle cx="87.4" cy="63" r=".25"/>
<circle cx="88.5" cy="70.2" r=".25"/>
<circle cx="89" cy="74.5" r=".25"/>
<circle cx="89" cy="67.1" r=".25"/>
<circle cx="89.2" cy="61" r=".25"/>
<circle cx="89.5" cy="72.8" r=".25"/>
<circle cx="89.8" cy="65.5" r=".25"/>
<circle cx="89.8" cy="73.7" r=".25"/>
<circle cx="90.8" cy="63.7" r=".25"/>
<circle cx="91.1" cy="70.9" r=".25"/>
<circle cx="91.8" cy="67.4" r=".25"/>
<circle cx="93.3" cy="77.3" r=".25"/>
<circle cx="93.9" cy="61" r=".25"/>
<circle cx="95.3" cy="69.1" r=".25"/>
<circle cx="95.8" cy="61.1" r=".25"/>
<circle cx="95.9" cy="66" r=".25"/>
<circle cx="97.5" cy="67.2" r=".25"/>
<circle cx="97.9" cy="75.8" r=".25"/>
<circle cx="98.3" cy="63.5" r=".25"/>
<circle cx="98.3" cy="73.3" r=".25"/>
<circle cx="99.3" cy="78.6" r=".25"/>
<circle cx="100.2" cy="60.3" r=".25"/>
<circle cx="100.2" cy="66" r=".25"/>
<circle cx="100.3" cy="74.5" r=".25"/>
<circle cx="100.8" cy="79.7" r=".25"/>
<circle cx="101.5" cy="63.5" r=".25"/>
<circle cx="101.5" cy="73.3" r=".25"/>
<circle cx="101.7" cy="70.6" r=".25"/>
<circle cx="101.9" cy="68.6" r=".25"/>
<circle cx="102" cy="60.3" r=".25"/>
<circle cx="102" cy="65.8" r=".25"/>
<circle cx="102.2" cy="76.1" r=".25"/>
<circle cx="103.1" cy="73.3" r=".25"/>
<circle cx="103.3" cy="79" r=".25"/>
<circle cx="103.3" cy="63.5" r=".25"/>
<circle cx="105.9" cy="69.1" r=".25"/>
<circle cx="107.8" cy="66.3" r=".7"/>
<circle cx="108.4" cy="67.8" r=".7"/>
<circle cx="108.7" cy="60.3" r=".25"/>
<circle cx="109.9" cy="68.4" r=".7"/>
<circle cx="109.9" cy="64.2" r=".7"/>
<circle cx="110.6" cy="60.3" r=".25"/>
<circle cx="111.3" cy="64.8" r=".7"/>
<circle cx="112" cy="66.3" r=".7"/>
<circle cx="112.6" cy="60.8" r=".25"/>
<circle cx="116" cy="66.8" r=".25"/>
<circle cx="116" cy="72.8" r=".25"/>
<circle cx="116" cy="78.8" r=".25"/>
<circle cx="116.1" cy="60.8" r=".25"/>
<circle cx="118" cy="65.8" r=".25"/>
<circle cx="118" cy="68.3" r=".25"/>
<circle cx="118.1" cy="74.3" r=".25"/>
<circle cx="118.1" cy="76.6" r=".25"/>
<circle cx="120.3" cy="74.3" r=".25"/>
<circle cx="120.8" cy="64.6" r=".25"/>
<circle cx="121.9" cy="65.8" r=".25"/>
<circle cx="121.9" cy="74.2" r=".25"/>
<circle cx="123.2" cy="74.3" r=".25"/>
<circle cx="123.3" cy="65.8" r=".25"/>
<circle cx="123.8" cy="77.6" r=".25"/>
<circle cx="125.2" cy="65.8" r=".25"/>
<circle cx="125.3" cy="74.3" r=".25"/>
<circle cx="126.2" cy="77.6" r=".25"/>
<circle cx="127" cy="65.8" r=".25"/>
<circle cx="127" cy="74.2" r=".25"/>
<circle cx="128.9" cy="74.3" r=".25"/>
<circle cx="129.4" cy="69" r=".25"/>
<circle cx="130.2" cy="76.7" r=".25"/>
<circle cx="130.9" cy="74.3" r=".25"/>
<circle cx="132.6" cy="74.2" r=".25"/>
<circle cx="132.8" cy="78.9" r=".25"/>
<circle cx="133.9" cy="74.3" r=".25"/>
<circle cx="134.1" cy="61.8" r=".5"/>
<circle cx="135.4" cy="68.3" r=".5"/>
<circle cx="136.1" cy="74.3" r=".25"/>
<circle cx="137.8" cy="74.3" r=".25"/>
<circle cx="140.6" cy="68.3" r=".5"/>
<circle cx="145.7" cy="76.6" r=".5"/>
<circle cx="145.7" cy="67.7" r=".5"/>
<circle cx="150.7" cy="71.7" r=".5"/>
<circle cx="153.3" cy="71.6" r=".25"/>
<circle cx="153.3" cy="77.3" r=".25"/>
<circle cx="157" cy="72.3" r=".5"/>
<circle cx="159.1" cy="76.8" r=".5"/>
<circle cx="165.4" cy="62.1" r=".5"/>
<circle cx="165.4" cy="60" r=".5"/>
<circle cx="167.3" cy="76.4" r=".5"/>
<circle cx="172.3" cy="75.7" r=".5"/>
<circle cx="172.8" cy="62" r=".5"/>
<circle cx="174.9" cy="71.5" r=".5"/>
<circle cx="174.9" cy="76.8" r=".5"/>
<circle cx="178.8" cy="61.1" r=".5"/>
<circle cx="179.2" cy="75.4" r=".25"/>
<circle cx="181.5" cy="69.8" r=".5"/>
<circle cx="181.7" cy="75.3" r=".5"/>
<circle cx="183.3" cy="78.4" r=".25"/>
<circle cx="184" cy="75.9" r=".25"/>
<circle cx="186.2" cy="61" r=".5"/>
<circle cx="189.2" cy="66.5" r=".5"/>
<circle cx="190.4" cy="75.3" r=".5"/>
<circle cx="193.3" cy="75.4" r=".5"/>
<circle cx="205" cy="66.7" r="1"/>
<circle cx="205" cy="61.5" r="1"/>
<circle cx="205" cy="77.1" r="1"/>
<circle cx="205" cy="71.9" r="1"/>
<circle cx="210.1" cy="66.7" r="1"/>
<circle cx="210.1" cy="61.5" r="1"/>
<circle cx="210.1" cy="77.1" r="1"/>
<circle cx="210.1" cy="71.9" r="1"/>
<circle cx="215.1" cy="71.9" r="1"/>
<circle cx="215.1" cy="77.1" r="1"/>
<circle cx="215.1" cy="66.7" r="1"/>
<circle cx="215.1" cy="61.5" r="1"/>
<circle cx="219.5" cy="78.7" r=".75"/>
<circle cx="219.5" cy="68.5" r=".75"/>
<circle cx="219.5" cy="66" r=".75"/>
<circle cx="219.5" cy="71" r=".75"/>
<circle cx="219.5" cy="60.9" r=".75"/>
<circle cx="219.5" cy="63.4" r=".75"/>
<circle cx="219.5" cy="73.6" r=".75"/>
<circle cx="219.5" cy="76.1" r=".75"/>
<circle cx="224.5" cy="68.5" r=".75"/>
<circle cx="224.5" cy="66" r=".75"/>
<circle cx="224.5" cy="73.6" r=".75"/>
<circle cx="224.5" cy="71" r=".75"/>
<circle cx="224.5" cy="78.7" r=".75"/>
<circle cx="224.5" cy="63.4" r=".75"/>
<circle cx="224.5" cy="76.1" r=".75"/>
<circle cx="224.5" cy="60.9" r=".75"/>
<circle cx="72" cy="84.8" r=".25"/>
<circle cx="72" cy="90.8" r=".25"/>
<circle cx="72.1" cy="96.8" r=".25"/>
<circle cx="73.3" cy="98" r=".25"/>
<circle cx="75.7" cy="87.7" r=".25"/>
<circle cx="75.7" cy="91.6" r=".25"/>
<circle cx="77.2" cy="80.5" r=".25"/>
<circle cx="77.3" cy="90.8" r=".25"/>
<circle cx="77.3" cy="87.1" r=".25"/>
<circle cx="77.3" cy="94.5" r=".25"/>
<circle cx="77.3" cy="93.2" r=".25"/>
<circle cx="77.3" cy="89.5" r=".25"/>
<circle cx="77.3" cy="85.8" r=".25"/>
<circle cx="78.4" cy="90.8" r=".25"/>
<circle cx="78.4" cy="87.1" r=".25"/>
<circle cx="78.4" cy="94.5" r=".25"/>
<circle cx="78.4" cy="89.5" r=".25"/>
<circle cx="78.4" cy="93.2" r=".25"/>
<circle cx="78.4" cy="85.8" r=".25"/>
<circle cx="79.1" cy="98" r=".25"/>
<circle cx="79.1" cy="87.5" r=".25"/>
<circle cx="79.4" cy="80.1" r=".25"/>
<circle cx="80.4" cy="80.3" r=".25"/>
<circle cx="80.9" cy="94.2" r=".25"/>
<circle cx="80.9" cy="86.9" r=".25"/>
<circle cx="84.3" cy="95.1" r=".25"/>
<circle cx="84.3" cy="89.4" r=".25"/>
<circle cx="85.1" cy="98" r=".25"/>
<circle cx="85.6" cy="85.6" r=".25"/>
<circle cx="86.1" cy="81.8" r=".25"/>
<circle cx="86.1" cy="95.1" r=".25"/>
<circle cx="86.1" cy="83.1" r=".25"/>
<circle cx="87.2" cy="92.6" r=".25"/>
<circle cx="87.4" cy="89.4" r=".25"/>
<circle cx="87.4" cy="85.6" r=".25"/>
<circle cx="87.4" cy="80.3" r=".25"/>
<circle cx="87.9" cy="83.1" r=".25"/>
<circle cx="89.2" cy="80.3" r=".25"/>
<circle cx="91.1" cy="81.8" r=".25"/>
<circle cx="91.1" cy="98" r=".25"/>
<circle cx="91.6" cy="90.2" r=".25"/>
<circle cx="91.6" cy="82.6" r=".25"/>
<circle cx="92.7" cy="88.4" r=".25"/>
<circle cx="92.7" cy="85.3" r=".25"/>
<circle cx="92.8" cy="89.5" r=".25"/>
<circle cx="93" cy="93.8" r=".25"/>
<circle cx="93" cy="86.6" r=".25"/>
<circle cx="93" cy="95.1" r=".25"/>
<circle cx="93.9" cy="87.6" r=".25"/>
<circle cx="94.7" cy="95.1" r=".25"/>
<circle cx="95.5" cy="89.5" r=".25"/>
<circle cx="95.6" cy="88.1" r=".25"/>
<circle cx="95.8" cy="85.7" r=".25"/>
<circle cx="95.9" cy="93.8" r=".25"/>
<circle cx="96" cy="92.6" r=".25"/>
<circle cx="96.1" cy="87.1" r=".25"/>
<circle cx="96.6" cy="82.9" r=".25"/>
<circle cx="97.1" cy="98" r=".25"/>
<circle cx="97.5" cy="90.2" r=".25"/>
<circle cx="98" cy="95.1" r=".25"/>
<circle cx="98.3" cy="85.7" r=".25"/>
<circle cx="98.6" cy="92.5" r=".25"/>
<circle cx="99.1" cy="82.8" r=".25"/>
<circle cx="100.2" cy="81.5" r=".25"/>
<circle cx="100.2" cy="93" r=".25"/>
<circle cx="100.6" cy="87.6" r=".25"/>
<circle cx="101" cy="89.9" r=".25"/>
<circle cx="101.2" cy="95" r=".25"/>
<circle cx="101.5" cy="82.9" r=".25"/>
<circle cx="102" cy="81.5" r=".25"/>
<circle cx="102.2" cy="92.2" r=".25"/>
<circle cx="102.9" cy="85.5" r=".25"/>
<circle cx="103.1" cy="98" r=".25"/>
<circle cx="103.3" cy="80.3" r=".25"/>
<circle cx="103.5" cy="90.8" r=".25"/>
<circle cx="104" cy="86.4" r=".25"/>
<circle cx="105.3" cy="91.9" r=".25"/>
<circle cx="105.3" cy="90.7" r=".25"/>
<circle cx="106.2" cy="87.4" r=".25"/>
<circle cx="107.7" cy="96.1" r=".25"/>
<circle cx="107.7" cy="92.2" r=".25"/>
<circle cx="107.8" cy="86.2" r=".25"/>
<circle cx="109.1" cy="98" r=".25"/>
<circle cx="109.3" cy="95.9" r=".25"/>
<circle cx="109.7" cy="92.1" r=".25"/>
<circle cx="111" cy="88.6" r=".25"/>
<circle cx="111.6" cy="90.2" r=".25"/>
<circle cx="114.8" cy="98" r=".25"/>
<circle cx="116" cy="90.8" r=".25"/>
<circle cx="116.1" cy="86" r=".25"/>
<circle cx="116.1" cy="96.8" r=".25"/>
<circle cx="117.9" cy="86.5" r=".25"/>
<circle cx="118" cy="98.7" r=".25"/>
<circle cx="118.1" cy="82.7" r=".25"/>
<circle cx="118.9" cy="96.1" r=".25"/>
<circle cx="119.6" cy="91.9" r=".25"/>
<circle cx="119.8" cy="97.8" r=".25"/>
<circle cx="120.4" cy="82.2" r=".25"/>
<circle cx="121.2" cy="86.5" r=".25"/>
<circle cx="121.5" cy="91.9" r=".25"/>
<circle cx="121.7" cy="81.3" r=".25"/>
<circle cx="122.7" cy="95.2" r=".25"/>
<circle cx="122.8" cy="86.5" r=".25"/>
<circle cx="123.2" cy="82.7" r=".25"/>
<circle cx="124.2" cy="91.1" r=".25"/>
<circle cx="127" cy="82.5" r=".25"/>
<circle cx="127.1" cy="92.2" r=".25"/>
<circle cx="127.1" cy="85.8" r=".25"/>
<circle cx="127.1" cy="96.3" r=".25"/>
<circle cx="128.8" cy="82.6" r=".25"/>
<circle cx="128.9" cy="92" r=".25"/>
<circle cx="129.4" cy="98.5" r=".25"/>
<circle cx="129.5" cy="90.7" r=".25"/>
<circle cx="130" cy="93" r=".25"/>
<circle cx="130" cy="97.1" r=".25"/>
<circle cx="130.6" cy="98.5" r=".25"/>
<circle cx="130.8" cy="82.5" r=".25"/>
<circle cx="131" cy="93" r=".25"/>
<circle cx="131.3" cy="91.2" r=".25"/>
<circle cx="131.4" cy="98.6" r=".25"/>
<circle cx="132.3" cy="86.5" r=".25"/>
<circle cx="132.6" cy="82.6" r=".25"/>
<circle cx="132.6" cy="95.6" r=".25"/>
<circle cx="133.7" cy="85.3" r=".25"/>
<circle cx="133.9" cy="82.7" r=".25"/>
<circle cx="135.3" cy="91.3" r=".25"/>
<circle cx="137.5" cy="82.7" r=".25"/>
<circle cx="139.1" cy="87.6" r=".25"/>
<circle cx="139.7" cy="91.6" r=".25"/>
<circle cx="140.1" cy="98.2" r=".25"/>
<circle cx="140.1" cy="99.4" r=".25"/>
<circle cx="140.5" cy="96" r=".25"/>
<circle cx="144.5" cy="87.4" r=".25"/>
<circle cx="144.5" cy="93" r=".25"/>
<circle cx="144.7" cy="99" r=".25"/>
<circle cx="145.9" cy="97" r=".25"/>
<circle cx="148.8" cy="97.6" r=".25"/>
<circle cx="148.8" cy="96.9" r=".25"/>
<circle cx="148.8" cy="96.3" r=".25"/>
<circle cx="150.2" cy="92" r=".25"/>
<circle cx="150.6" cy="91.1" r=".25"/>
<circle cx="150.6" cy="98.2" r=".25"/>
<circle cx="150.7" cy="94.4" r=".25"/>
<circle cx="154.2" cy="94.7" r=".25"/>
<circle cx="154.6" cy="98.2" r=".25"/>
<circle cx="154.7" cy="91.1" r=".25"/>
<circle cx="154.8" cy="97.5" r=".25"/>
<circle cx="154.8" cy="96.9" r=".25"/>
<circle cx="154.8" cy="96.3" r=".25"/>
<circle cx="155.6" cy="90.9" r=".25"/>
<circle cx="155.6" cy="92.6" r=".25"/>
<circle cx="160.7" cy="95.9" r=".25"/>
<circle cx="160.7" cy="90.7" r=".25"/>
<circle cx="160.7" cy="98.5" r=".25"/>
<circle cx="160.8" cy="97.1" r=".25"/>
<circle cx="161" cy="91.9" r=".25"/>
<circle cx="161.1" cy="99.2" r=".25"/>
<circle cx="161.1" cy="93.1" r=".25"/>
<circle cx="161.2" cy="96.4" r=".25"/>
<circle cx="161.4" cy="91.3" r=".25"/>
<circle cx="161.5" cy="90" r=".25"/>
<circle cx="161.7" cy="98.6" r=".25"/>
<circle cx="162.2" cy="89.4" r=".25"/>
<circle cx="163.8" cy="98.4" r=".25"/>
<circle cx="167.7" cy="93.7" r=".25"/>
<circle cx="168.3" cy="91.3" r=".25"/>
<circle cx="168.3" cy="89.3" r=".25"/>
<circle cx="168.3" cy="90" r=".25"/>
<circle cx="168.4" cy="95.9" r=".25"/>
<circle cx="168.4" cy="97.8" r=".25"/>
<circle cx="174" cy="96.9" r=".25"/>
<circle cx="174" cy="92.8" r=".25"/>
<circle cx="175.9" cy="81.8" r=".5"/>
<circle cx="178" cy="92.6" r=".25"/>
<circle cx="178.7" cy="82.8" r=".5"/>
<circle cx="182.5" cy="90.4" r=".25"/>
<circle cx="182.5" cy="89.1" r=".25"/>
<circle cx="182.6" cy="98" r=".25"/>
<circle cx="188.8" cy="90.4" r=".25"/>
<circle cx="189" cy="89.1" r=".25"/>
<circle cx="189.2" cy="96.8" r=".25"/>
<circle cx="189.2" cy="98" r=".25"/>
<circle cx="194.9" cy="90.9" r=".25"/>
<circle cx="195.3" cy="97.1" r=".25"/>
<circle cx="198.9" cy="90.3" r=".25"/>
<circle cx="198.9" cy="92.2" r=".25"/>
<circle cx="198.9" cy="94.1" r=".25"/>
<circle cx="202.6" cy="97.8" r=".25"/>
<circle cx="204.9" cy="91.7" r=".25"/>
<circle cx="205.6" cy="85.2" r=".25"/>
<circle cx="205.7" cy="83.9" r=".25"/>
<circle cx="205.7" cy="83.3" r=".25"/>
<circle cx="205.7" cy="81.9" r=".25"/>
<circle cx="205.7" cy="81.3" r=".25"/>
<circle cx="205.7" cy="82.6" r=".25"/>
<circle cx="206.1" cy="91.7" r=".25"/>
<circle cx="209.4" cy="85.2" r=".25"/>
<circle cx="210.8" cy="90.2" r=".25"/>
<circle cx="219.5" cy="93.9" r=".75"/>
<circle cx="219.5" cy="81.2" r=".75"/>
<circle cx="219.5" cy="83.7" r=".75"/>
<circle cx="219.5" cy="91.4" r=".75"/>
<circle cx="219.5" cy="88.8" r=".75"/>
<circle cx="219.5" cy="99" r=".75"/>
<circle cx="219.5" cy="96.4" r=".75"/>
<circle cx="219.5" cy="86.3" r=".75"/>
<circle cx="224.5" cy="88.8" r=".75"/>
<circle cx="224.5" cy="93.9" r=".75"/>
<circle cx="224.5" cy="99" r=".75"/>
<circle cx="224.5" cy="86.3" r=".75"/>
<circle cx="224.5" cy="96.4" r=".75"/>
<circle cx="224.5" cy="81.2" r=".75"/>
<circle cx="224.5" cy="83.7" r=".75"/>
<circle cx="224.5" cy="91.4" r=".75"/>
<circle cx="78.1" cy="115.8" r=".5"/>
<circle cx="78.1" cy="118.4" r=".5"/>
<circle cx="80.5" cy="118.4" r=".5"/>
<circle cx="80.5" cy="115.8" r=".5"/>
<circle cx="83.1" cy="118.4" r=".5"/>
<circle cx="83.1" cy="115.8" r=".5"/>
<circle cx="83.4" cy="102.4" r=".25"/>
<circle cx="98.4" cy="118.4" r=".5"/>
<circle cx="98.4" cy="115.8" r=".5"/>
<circle cx="101" cy="118.4" r=".5"/>
<circle cx="101" cy="115.7" r=".5"/>
<circle cx="103.5" cy="118.4" r=".5"/>
<circle cx="103.5" cy="115.7" r=".5"/>
<circle cx="112.5" cy="109.2" r=".25"/>
<circle cx="113.8" cy="114.8" r=".25"/>
<circle cx="114" cy="111.1" r=".25"/>
<circle cx="114" cy="109.7" r=".25"/>
<circle cx="114" cy="110.5" r=".25"/>
<circle cx="114" cy="109" r=".25"/>
<circle cx="114" cy="111.8" r=".25"/>
<circle cx="114.9" cy="113.7" r=".25"/>
<circle cx="115.5" cy="105.5" r=".25"/>
<circle cx="115.6" cy="107.4" r=".25"/>
<circle cx="116" cy="106.7" r=".25"/>
<circle cx="116.8" cy="104.6" r=".25"/>
<circle cx="117.1" cy="113.7" r=".25"/>
<circle cx="117.5" cy="107.8" r=".25"/>
<circle cx="117.6" cy="104.8" r=".25"/>
<circle cx="117.7" cy="100.5" r=".25"/>
<circle cx="118" cy="103.8" r=".25"/>
<circle cx="118.1" cy="114.8" r=".25"/>
<circle cx="119.5" cy="106.5" r=".25"/>
<circle cx="120.2" cy="111.2" r=".25"/>
<circle cx="120.3" cy="109.2" r=".25"/>
<circle cx="120.3" cy="110.2" r=".25"/>
<circle cx="120.3" cy="112.2" r=".25"/>
<circle cx="120.5" cy="100.5" r=".25"/>
<circle cx="120.9" cy="107.8" r=".25"/>
<circle cx="121.4" cy="106.4" r=".25"/>
<circle cx="121.5" cy="105.4" r=".25"/>
<circle cx="122.6" cy="112" r=".25"/>
<circle cx="124.5" cy="117.1" r=".25"/>
<circle cx="128.1" cy="118.4" r=".25"/>
<circle cx="128.3" cy="115.6" r=".25"/>
<circle cx="129" cy="118.4" r=".25"/>
<circle cx="129.5" cy="108.6" r=".25"/>
<circle cx="130.7" cy="108.5" r=".25"/>
<circle cx="131.6" cy="104.8" r=".25"/>
<circle cx="131.8" cy="112.4" r=".25"/>
<circle cx="131.8" cy="101.5" r=".25"/>
<circle cx="132.3" cy="104.8" r=".25"/>
<circle cx="133.7" cy="108.6" r=".25"/>
<circle cx="134.2" cy="118.7" r=".25"/>
<circle cx="137" cy="119.9" r=".25"/>
<circle cx="137" cy="118.1" r=".25"/>
<circle cx="139.7" cy="108.3" r=".25"/>
<circle cx="140.2" cy="116.9" r=".25"/>
<circle cx="141.5" cy="119.2" r=".25"/>
<circle cx="141.5" cy="113.2" r=".25"/>
<circle cx="142.5" cy="108.6" r=".25"/>
<circle cx="144.5" cy="108.6" r=".25"/>
<circle cx="145.4" cy="102.9" r=".25"/>
<circle cx="146.2" cy="109.2" r=".25"/>
<circle cx="146.3" cy="110.9" r=".25"/>
<circle cx="146.4" cy="115.2" r=".25"/>
<circle cx="146.4" cy="110.2" r=".25"/>
<circle cx="148.7" cy="117.7" r=".25"/>
<circle cx="148.7" cy="118.7" r=".25"/>
<circle cx="148.9" cy="102.2" r=".25"/>
<circle cx="148.9" cy="103.6" r=".25"/>
<circle cx="149" cy="114.7" r=".25"/>
<circle cx="149.1" cy="119.2" r=".25"/>
<circle cx="149.5" cy="108.5" r=".25"/>
<circle cx="150.4" cy="113.5" r=".25"/>
<circle cx="150.5" cy="102.9" r=".25"/>
<circle cx="150.5" cy="111" r=".25"/>
<circle cx="150.5" cy="110.2" r=".25"/>
<circle cx="150.7" cy="104.1" r=".25"/>
<circle cx="150.7" cy="108.5" r=".25"/>
<circle cx="150.7" cy="100.2" r=".25"/>
<circle cx="151" cy="106.3" r=".25"/>
<circle cx="151.1" cy="113.5" r=".25"/>
<circle cx="151.4" cy="114.5" r=".25"/>
<circle cx="151.5" cy="101.7" r=".25"/>
<circle cx="152" cy="114.4" r=".25"/>
<circle cx="152.5" cy="115.1" r=".25"/>
<circle cx="152.9" cy="114.4" r=".25"/>
<circle cx="153" cy="105.8" r=".25"/>
<circle cx="153.4" cy="113" r=".25"/>
<circle cx="153.5" cy="106.2" r=".25"/>
<circle cx="153.8" cy="101.7" r=".25"/>
<circle cx="153.9" cy="105.8" r=".25"/>
<circle cx="153.9" cy="114.4" r=".25"/>
<circle cx="154.2" cy="113.3" r=".25"/>
<circle cx="154.3" cy="119.1" r=".25"/>
<circle cx="154.4" cy="106.3" r=".25"/>
<circle cx="154.6" cy="108.6" r=".25"/>
<circle cx="154.6" cy="104.1" r=".25"/>
<circle cx="155" cy="106" r=".25"/>
<circle cx="155.1" cy="114.4" r=".25"/>
<circle cx="155.1" cy="113" r=".25"/>
<circle cx="155.6" cy="106.3" r=".25"/>
<circle cx="155.8" cy="113" r=".25"/>
<circle cx="156" cy="108.5" r=".25"/>
<circle cx="156.6" cy="111.8" r=".25"/>
<circle cx="156.6" cy="113.8" r=".25"/>
<circle cx="157.1" cy="108.3" r=".25"/>
<circle cx="157.2" cy="105.7" r=".25"/>
<circle cx="157.2" cy="113.8" r=".25"/>
<circle cx="157.4" cy="118.2" r=".25"/>
<circle cx="157.5" cy="113.1" r=".25"/>
<circle cx="157.9" cy="105.7" r=".25"/>
<circle cx="158.2" cy="113.3" r=".25"/>
<circle cx="158.4" cy="119.4" r=".25"/>
<circle cx="158.5" cy="106.3" r=".25"/>
<circle cx="158.5" cy="108.6" r=".25"/>
<circle cx="158.5" cy="118.8" r=".25"/>
<circle cx="158.7" cy="116.1" r=".25"/>
<circle cx="159" cy="108.2" r=".25"/>
<circle cx="159.1" cy="119.5" r=".25"/>
<circle cx="159.3" cy="105.7" r=".25"/>
<circle cx="159.9" cy="105.7" r=".25"/>
<circle cx="160.4" cy="109.6" r=".25"/>
<circle cx="160.4" cy="108.8" r=".25"/>
<circle cx="160.4" cy="115.4" r=".25"/>
<circle cx="160.4" cy="117.8" r=".25"/>
<circle cx="160.8" cy="105.3" r=".25"/>
<circle cx="161.2" cy="117.2" r=".25"/>
<circle cx="161.5" cy="102.4" r=".25"/>
<circle cx="161.7" cy="108.5" r=".25"/>
<circle cx="161.9" cy="102.9" r=".25"/>
<circle cx="162" cy="104.3" r=".25"/>
<circle cx="163.6" cy="105.9" r=".25"/>
<circle cx="165.1" cy="103" r=".25"/>
<circle cx="165.2" cy="106" r=".25"/>
<circle cx="165.7" cy="117.3" r=".25"/>
<circle cx="166.4" cy="119.9" r=".25"/>
<circle cx="167.6" cy="114.5" r=".25"/>
<circle cx="167.8" cy="113.3" r=".25"/>
<circle cx="167.9" cy="119.2" r=".25"/>
<circle cx="167.9" cy="109.2" r=".25"/>
<circle cx="170.2" cy="115.4" r=".25"/>
<circle cx="170.3" cy="114.2" r=".25"/>
<circle cx="173.1" cy="109.7" r=".25"/>
<circle cx="173.1" cy="114" r=".25"/>
<circle cx="173.4" cy="113.4" r=".25"/>
<circle cx="173.5" cy="108.1" r=".25"/>
<circle cx="174.6" cy="102.4" r=".25"/>
<circle cx="175.3" cy="107.3" r=".25"/>
<circle cx="175.3" cy="108.8" r=".25"/>
<circle cx="175.3" cy="105.8" r=".25"/>
<circle cx="175.3" cy="111.9" r=".25"/>
<circle cx="176.1" cy="102.4" r=".25"/>
<circle cx="177.7" cy="108.3" r=".25"/>
<circle cx="177.9" cy="114.9" r=".25"/>
<circle cx="178.6" cy="111.5" r=".25"/>
<circle cx="178.8" cy="116.1" r=".25"/>
<circle cx="178.8" cy="112.5" r=".25"/>
<circle cx="179.3" cy="108.6" r=".25"/>
<circle cx="179.3" cy="109.6" r=".25"/>
<circle cx="179.3" cy="107.5" r=".25"/>
<circle cx="180.1" cy="112" r=".25"/>
<circle cx="180.3" cy="108.6" r=".25"/>
<circle cx="180.3" cy="109.6" r=".25"/>
<circle cx="180.3" cy="107.5" r=".25"/>
<circle cx="180.5" cy="103.9" r=".25"/>
<circle cx="180.5" cy="101.8" r=".25"/>
<circle cx="180.6" cy="111.2" r=".25"/>
<circle cx="181" cy="111.8" r=".25"/>
<circle cx="181.4" cy="108.6" r=".25"/>
<circle cx="181.4" cy="109.6" r=".25"/>
<circle cx="181.4" cy="107.5" r=".25"/>
<circle cx="181.5" cy="104.8" r=".25"/>
<circle cx="181.6" cy="111.4" r=".25"/>
<circle cx="181.9" cy="113.2" r=".25"/>
<circle cx="182.1" cy="106.9" r=".25"/>
<circle cx="183" cy="101.8" r=".25"/>
<circle cx="183.3" cy="106.3" r=".25"/>
<circle cx="183.3" cy="110.4" r=".25"/>
<circle cx="183.5" cy="113.2" r=".25"/>
<circle cx="183.8" cy="107" r=".25"/>
<circle cx="184.3" cy="107.6" r=".25"/>
<circle cx="186.1" cy="115.1" r=".5"/>
<circle cx="187.7" cy="106.5" r=".25"/>
<circle cx="187.7" cy="110.4" r=".25"/>
<circle cx="187.7" cy="112.9" r=".25"/>
<circle cx="187.7" cy="104" r=".25"/>
<circle cx="189.9" cy="111.6" r=".25"/>
<circle cx="189.9" cy="105.3" r=".25"/>
<circle cx="196.5" cy="111.6" r=".25"/>
<circle cx="196.5" cy="105.3" r=".25"/>
<circle cx="207" cy="119.2" r=".5"/>
<circle cx="219.5" cy="104.1" r=".75"/>
<circle cx="219.5" cy="106.6" r=".75"/>
<circle cx="219.5" cy="114.2" r=".75"/>
<circle cx="219.5" cy="116.8" r=".75"/>
<circle cx="219.5" cy="101.5" r=".75"/>
<circle cx="219.5" cy="111.7" r=".75"/>
<circle cx="219.5" cy="119.3" r=".75"/>
<circle cx="219.5" cy="109.1" r=".75"/>
<circle cx="224.5" cy="109.1" r=".75"/>
<circle cx="224.5" cy="119.3" r=".75"/>
<circle cx="224.5" cy="101.5" r=".75"/>
<circle cx="224.5" cy="111.7" r=".75"/>
<circle cx="224.5" cy="106.6" r=".75"/>
<circle cx="224.5" cy="116.8" r=".75"/>
<circle cx="224.5" cy="104.1" r=".75"/>
<circle cx="224.5" cy="114.2" r=".75"/>
<circle cx="73.7" cy="134.1" r=".25"/>
<circle cx="75.3" cy="129.5" r=".25"/>
<circle cx="75.3" cy="130.4" r=".25"/>
<circle cx="75.3" cy="128.6" r=".25"/>
<circle cx="76.2" cy="130.4" r=".25"/>
<circle cx="76.2" cy="129.5" r=".25"/>
<circle cx="76.2" cy="128.6" r=".25"/>
<circle cx="77" cy="134.1" r=".25"/>
<circle cx="77.9" cy="139.7" r=".25"/>
<circle cx="77.9" cy="137.9" r=".25"/>
<circle cx="77.9" cy="137" r=".25"/>
<circle cx="77.9" cy="136.1" r=".25"/>
<circle cx="77.9" cy="138.8" r=".25"/>
<circle cx="78.1" cy="120.9" r=".5"/>
<circle cx="78.7" cy="134.4" r=".5"/>
<circle cx="78.7" cy="133.1" r=".5"/>
<circle cx="80" cy="133.1" r=".5"/>
<circle cx="80" cy="134.4" r=".5"/>
<circle cx="80" cy="136.1" r=".25"/>
<circle cx="80" cy="139.7" r=".25"/>
<circle cx="80" cy="137" r=".25"/>
<circle cx="80" cy="138.8" r=".25"/>
<circle cx="80" cy="137.9" r=".25"/>
<circle cx="80.5" cy="120.9" r=".5"/>
<circle cx="80.9" cy="136.1" r=".25"/>
<circle cx="80.9" cy="139.7" r=".25"/>
<circle cx="81.8" cy="139.7" r=".25"/>
<circle cx="83.1" cy="120.9" r=".5"/>
<circle cx="85.5" cy="136.6" r=".25"/>
<circle cx="85.5" cy="137.9" r=".25"/>
<circle cx="85.5" cy="139.2" r=".25"/>
<circle cx="85.7" cy="133.1" r=".5"/>
<circle cx="85.7" cy="134.4" r=".5"/>
<circle cx="87.1" cy="126.1" r=".5"/>
<circle cx="87.1" cy="127.4" r=".5"/>
<circle cx="87.1" cy="131.2" r=".5"/>
<circle cx="87.1" cy="128.6" r=".5"/>
<circle cx="87.1" cy="133.1" r=".5"/>
<circle cx="87.1" cy="134.4" r=".5"/>
<circle cx="87.1" cy="129.9" r=".5"/>
<circle cx="88.4" cy="126.1" r=".5"/>
<circle cx="88.4" cy="127.4" r=".5"/>
<circle cx="88.4" cy="128.6" r=".5"/>
<circle cx="88.4" cy="136.5" r=".5"/>
<circle cx="88.4" cy="133.1" r=".5"/>
<circle cx="88.4" cy="131.2" r=".5"/>
<circle cx="88.4" cy="137.8" r=".5"/>
<circle cx="88.4" cy="134.4" r=".5"/>
<circle cx="88.4" cy="129.9" r=".5"/>
<circle cx="89.7" cy="126.1" r=".5"/>
<circle cx="89.7" cy="127.4" r=".5"/>
<circle cx="89.7" cy="128.6" r=".5"/>
<circle cx="89.7" cy="131.2" r=".5"/>
<circle cx="89.7" cy="129.9" r=".5"/>
<circle cx="89.7" cy="134.4" r=".5"/>
<circle cx="89.7" cy="133.1" r=".5"/>
<circle cx="89.7" cy="137.8" r=".5"/>
<circle cx="89.7" cy="136.5" r=".5"/>
<circle cx="91.7" cy="137.8" r=".5"/>
<circle cx="91.7" cy="139.1" r=".5"/>
<circle cx="91.7" cy="136.5" r=".5"/>
<circle cx="91.8" cy="126.1" r=".5"/>
<circle cx="91.8" cy="127.4" r=".5"/>
<circle cx="91.8" cy="128.6" r=".5"/>
<circle cx="91.8" cy="131.2" r=".5"/>
<circle cx="91.8" cy="129.9" r=".5"/>
<circle cx="93" cy="139.1" r=".5"/>
<circle cx="93" cy="137.8" r=".5"/>
<circle cx="93" cy="136.5" r=".5"/>
<circle cx="93.1" cy="126.1" r=".5"/>
<circle cx="93.1" cy="127.4" r=".5"/>
<circle cx="93.1" cy="128.6" r=".5"/>
<circle cx="93.1" cy="131.2" r=".5"/>
<circle cx="93.1" cy="129.9" r=".5"/>
<circle cx="94.4" cy="126.1" r=".5"/>
<circle cx="94.4" cy="127.4" r=".5"/>
<circle cx="94.4" cy="128.6" r=".5"/>
<circle cx="94.4" cy="131.2" r=".5"/>
<circle cx="94.4" cy="129.9" r=".5"/>
<circle cx="97.2" cy="136.3" r=".25"/>
<circle cx="97.2" cy="135.2" r=".25"/>
<circle cx="97.2" cy="139.7" r=".25"/>
<circle cx="98.2" cy="135.2" r=".25"/>
<circle cx="98.4" cy="120.9" r=".5"/>
<circle cx="99.2" cy="135.2" r=".25"/>
<circle cx="100.2" cy="135.2" r=".25"/>
<circle cx="101" cy="120.9" r=".5"/>
<circle cx="101.2" cy="139.7" r=".25"/>
<circle cx="101.2" cy="135.2" r=".25"/>
<circle cx="101.2" cy="136.3" r=".25"/>
<circle cx="103.5" cy="120.9" r=".5"/>
<circle cx="104.6" cy="136.9" r=".25"/>
<circle cx="104.6" cy="137.9" r=".25"/>
<circle cx="104.6" cy="138.9" r=".25"/>
<circle cx="106.3" cy="137.9" r=".25"/>
<circle cx="107.4" cy="126.1" r=".5"/>
<circle cx="107.4" cy="127.4" r=".5"/>
<circle cx="107.4" cy="131.2" r=".5"/>
<circle cx="107.4" cy="128.6" r=".5"/>
<circle cx="107.4" cy="129.9" r=".5"/>
<circle cx="107.9" cy="138.9" r=".25"/>
<circle cx="107.9" cy="137.9" r=".25"/>
<circle cx="107.9" cy="136.9" r=".25"/>
<circle cx="108.7" cy="126.1" r=".5"/>
<circle cx="108.7" cy="127.4" r=".5"/>
<circle cx="108.7" cy="128.6" r=".5"/>
<circle cx="108.7" cy="129.9" r=".5"/>
<circle cx="108.7" cy="131.2" r=".5"/>
<circle cx="110" cy="126.1" r=".5"/>
<circle cx="110" cy="127.4" r=".5"/>
<circle cx="110" cy="131.2" r=".5"/>
<circle cx="110" cy="128.6" r=".5"/>
<circle cx="110" cy="129.9" r=".5"/>
<circle cx="111.8" cy="134.9" r=".25"/>
<circle cx="111.8" cy="133.9" r=".25"/>
<circle cx="111.8" cy="135.9" r=".25"/>
<circle cx="112.8" cy="133.9" r=".25"/>
<circle cx="112.8" cy="135.9" r=".25"/>
<circle cx="112.8" cy="134.9" r=".25"/>
<circle cx="112.9" cy="126.5" r=".25"/>
<circle cx="119.5" cy="135.4" r=".25"/>
<circle cx="120.3" cy="135.4" r=".25"/>
<circle cx="120.4" cy="132.1" r=".25"/>
<circle cx="121.5" cy="137.4" r=".25"/>
<circle cx="122.6" cy="137.4" r=".25"/>
<circle cx="122.8" cy="120.3" r=".25"/>
<circle cx="122.8" cy="124.6" r=".25"/>
<circle cx="122.8" cy="123.5" r=".25"/>
<circle cx="123.6" cy="133.4" r=".25"/>
<circle cx="123.6" cy="137.4" r=".25"/>
<circle cx="124" cy="121" r=".25"/>
<circle cx="124.3" cy="125.1" r=".25"/>
<circle cx="124.7" cy="127.5" r=".25"/>
<circle cx="125.2" cy="124.2" r=".25"/>
<circle cx="125.5" cy="135.9" r=".25"/>
<circle cx="127.8" cy="127.5" r=".25"/>
<circle cx="130.7" cy="127.5" r=".25"/>
<circle cx="131.6" cy="124.5" r=".25"/>
<circle cx="131.8" cy="127.5" r=".25"/>
<circle cx="132.8" cy="120.3" r=".25"/>
<circle cx="133.2" cy="124.3" r=".25"/>
<circle cx="133.2" cy="127.5" r=".25"/>
<circle cx="133.3" cy="122.2" r=".25"/>
<circle cx="134.5" cy="127.4" r=".25"/>
<circle cx="135.6" cy="124.3" r=".25"/>
<circle cx="136.8" cy="124.2" r=".25"/>
<circle cx="137" cy="123.4" r=".25"/>
<circle cx="137.3" cy="129.9" r=".25"/>
<circle cx="137.7" cy="127.5" r=".25"/>
<circle cx="138.7" cy="135.6" r=".25"/>
<circle cx="138.7" cy="136.6" r=".25"/>
<circle cx="138.7" cy="138.7" r=".25"/>
<circle cx="138.7" cy="137.7" r=".25"/>
<circle cx="138.7" cy="133.6" r=".25"/>
<circle cx="138.7" cy="134.6" r=".25"/>
<circle cx="138.7" cy="132.6" r=".25"/>
<circle cx="139.7" cy="133.6" r=".25"/>
<circle cx="139.7" cy="138.7" r=".25"/>
<circle cx="139.7" cy="134.6" r=".25"/>
<circle cx="139.7" cy="132.6" r=".25"/>
<circle cx="139.7" cy="137.7" r=".25"/>
<circle cx="139.7" cy="136.6" r=".25"/>
<circle cx="139.7" cy="135.6" r=".25"/>
<circle cx="140.2" cy="123.6" r=".25"/>
<circle cx="140.7" cy="127.6" r=".25"/>
<circle cx="141.6" cy="126.7" r=".25"/>
<circle cx="142.1" cy="132.3" r=".25"/>
<circle cx="142.1" cy="129" r=".25"/>
<circle cx="142.2" cy="133.6" r=".25"/>
<circle cx="144.7" cy="129" r=".25"/>
<circle cx="145.6" cy="122.3" r=".25"/>
<circle cx="146.4" cy="126.5" r=".25"/>
<circle cx="146.4" cy="120.2" r=".25"/>
<circle cx="147.3" cy="129" r=".25"/>
<circle cx="149" cy="120.1" r=".25"/>
<circle cx="149.1" cy="125.7" r=".25"/>
<circle cx="149.2" cy="129.8" r=".25"/>
<circle cx="149.4" cy="124.6" r=".25"/>
<circle cx="149.7" cy="122.2" r=".25"/>
<circle cx="149.9" cy="129.8" r=".25"/>
<circle cx="150.5" cy="129.8" r=".25"/>
<circle cx="151.1" cy="129.8" r=".25"/>
<circle cx="151.8" cy="129.8" r=".25"/>
<circle cx="151.9" cy="122.2" r=".25"/>
<circle cx="152.5" cy="129.7" r=".25"/>
<circle cx="152.9" cy="127.4" r=".25"/>
<circle cx="153" cy="130.1" r=".25"/>
<circle cx="153.5" cy="129.7" r=".25"/>
<circle cx="154.3" cy="120.1" r=".25"/>
<circle cx="154.5" cy="130" r=".25"/>
<circle cx="154.8" cy="130.6" r=".25"/>
<circle cx="155.4" cy="130.1" r=".25"/>
<circle cx="155.4" cy="131" r=".25"/>
<circle cx="156.6" cy="126.5" r=".25"/>
<circle cx="156.9" cy="122.8" r=".25"/>
<circle cx="157" cy="129.7" r=".25"/>
<circle cx="158.1" cy="127.5" r=".25"/>
<circle cx="158.5" cy="125.1" r=".25"/>
<circle cx="158.8" cy="120.2" r=".25"/>
<circle cx="159.5" cy="121.8" r=".25"/>
<circle cx="159.5" cy="121.2" r=".25"/>
<circle cx="160.3" cy="127.5" r=".25"/>
<circle cx="160.7" cy="122.7" r=".25"/>
<circle cx="160.7" cy="124.5" r=".25"/>
<circle cx="160.9" cy="127.5" r=".25"/>
<circle cx="161.4" cy="136.6" r=".25"/>
<circle cx="161.4" cy="135.6" r=".25"/>
<circle cx="161.4" cy="134.6" r=".25"/>
<circle cx="161.4" cy="137.7" r=".25"/>
<circle cx="161.4" cy="138.7" r=".25"/>
<circle cx="161.4" cy="133.6" r=".25"/>
<circle cx="161.5" cy="127.5" r=".25"/>
<circle cx="162.2" cy="120.5" r=".25"/>
<circle cx="162.4" cy="126" r=".25"/>
<circle cx="162.4" cy="138.7" r=".25"/>
<circle cx="162.4" cy="135.6" r=".25"/>
<circle cx="162.4" cy="134.6" r=".25"/>
<circle cx="162.4" cy="137.7" r=".25"/>
<circle cx="162.4" cy="136.6" r=".25"/>
<circle cx="162.4" cy="133.6" r=".25"/>
<circle cx="162.4" cy="127.5" r=".25"/>
<circle cx="163.1" cy="122.9" r=".25"/>
<circle cx="163.8" cy="122.9" r=".25"/>
<circle cx="164.1" cy="127.6" r=".25"/>
<circle cx="164.6" cy="122.9" r=".25"/>
<circle cx="165.2" cy="129.8" r=".25"/>
<circle cx="165.4" cy="123" r=".25"/>
<circle cx="166.2" cy="122.9" r=".25"/>
<circle cx="166.5" cy="127.6" r=".25"/>
<circle cx="166.5" cy="132.8" r=".25"/>
<circle cx="167" cy="127.2" r=".25"/>
<circle cx="167.7" cy="120.8" r=".25"/>
<circle cx="168.4" cy="137.2" r=".25"/>
<circle cx="170.1" cy="125.1" r=".25"/>
<circle cx="176.1" cy="131.8" r="1.1"/>
<circle cx="176.1" cy="121.7" r="1.1"/>
<circle cx="196.5" cy="129.3" r="1.1"/>
<circle cx="196.5" cy="134.4" r="1.1"/>
<circle cx="205" cy="134.9" r="1.15"/>
<circle cx="207" cy="120.5" r=".5"/>
<circle cx="207" cy="121.8" r=".5"/>
<circle cx="209.5" cy="134.9" r="1.15"/>
<circle cx="213.4" cy="120.1" r=".5"/>
<circle cx="219.5" cy="126.9" r=".75"/>
<circle cx="219.5" cy="129.5" r=".75"/>
<circle cx="219.5" cy="139.6" r=".75"/>
<circle cx="219.5" cy="137.1" r=".75"/>
<circle cx="219.5" cy="132" r=".75"/>
<circle cx="219.5" cy="134.5" r=".75"/>
<circle cx="219.5" cy="124.4" r=".75"/>
<circle cx="219.5" cy="121.8" r=".75"/>
<circle cx="224.5" cy="126.9" r=".75"/>
<circle cx="224.5" cy="132" r=".75"/>
<circle cx="224.5" cy="129.5" r=".75"/>
<circle cx="224.5" cy="137.1" r=".75"/>
<circle cx="224.5" cy="139.6" r=".75"/>
<circle cx="224.5" cy="134.5" r=".75"/>
<circle cx="224.5" cy="121.8" r=".75"/>
<circle cx="224.5" cy="124.4" r=".75"/>
<circle cx="75.3" cy="141.9" r=".25"/>
<circle cx="77.6" cy="143.5" r=".5"/>
<circle cx="81.4" cy="147.1" r=".5"/>
<circle cx="82.8" cy="143.5" r=".5"/>
<circle cx="82.8" cy="147.1" r=".5"/>
<circle cx="84.1" cy="147.1" r=".5"/>
<circle cx="84.1" cy="143.5" r=".5"/>
<circle cx="95.1" cy="146.9" r=".25"/>
<circle cx="95.1" cy="143.6" r=".25"/>
<circle cx="97.2" cy="140.7" r=".25"/>
<circle cx="98.2" cy="140.7" r=".25"/>
<circle cx="99.2" cy="140.7" r=".25"/>
<circle cx="100.2" cy="140.7" r=".25"/>
<circle cx="101.2" cy="140.7" r=".25"/>
<circle cx="103.1" cy="145.3" r=".25"/>
<circle cx="104.5" cy="143.1" r=".5"/>
<circle cx="111.8" cy="140.7" r=".25"/>
<circle cx="111.8" cy="141.7" r=".25"/>
<circle cx="111.8" cy="142.7" r=".25"/>
<circle cx="112.8" cy="141.7" r=".25"/>
<circle cx="112.8" cy="142.7" r=".25"/>
<circle cx="112.8" cy="140.7" r=".25"/>
<circle cx="119.8" cy="143.8" r=".25"/>
<circle cx="120.3" cy="141.2" r=".25"/>
<circle cx="123.6" cy="141.2" r=".25"/>
<circle cx="123.6" cy="142.2" r=".25"/>
<circle cx="124.8" cy="141.2" r=".25"/>
<circle cx="131.1" cy="141.9" r=".6"/>
<circle cx="133.6" cy="141.9" r=".6"/>
<circle cx="145.2" cy="145.4" r=".5"/>
<circle cx="145.2" cy="146.9" r=".5"/>
<circle cx="146.4" cy="146.9" r=".5"/>
<circle cx="147.7" cy="146.9" r=".5"/>
<circle cx="152.1" cy="141.9" r=".6"/>
<circle cx="154.7" cy="141.9" r=".6"/>
<circle cx="167" cy="146.8" r=".5"/>
<circle cx="168.3" cy="146.8" r=".5"/>
<circle cx="169.5" cy="146.8" r=".5"/>
<circle cx="176.1" cy="142" r="1.1"/>
<circle cx="196.5" cy="142" r="1.1"/>
<circle cx="205" cy="144.9" r="1.15"/>
<circle cx="209.5" cy="144.9" r="1.15"/>
<circle cx="212" cy="145.3" r=".25"/>
<circle cx="212" cy="141.5" r=".25"/>
<circle cx="212" cy="144" r=".25"/>
<circle cx="212" cy="146.6" r=".25"/>
<circle cx="212" cy="142.7" r=".25"/>
<circle cx="216.2" cy="145.3" r=".25"/>
<circle cx="216.2" cy="141.5" r=".25"/>
<circle cx="216.2" cy="144" r=".25"/>
<circle cx="216.2" cy="146.6" r=".25"/>
<circle cx="216.2" cy="142.7" r=".25"/>
<circle cx="217.7" cy="144" r=".5"/>
<circle cx="227.1" cy="144.7" r="2.05"/>
</g>
<g fill="#000">
<circle cx="90.4" cy="105.9" r=".6"/>
<circle cx="90.4" cy="103.4" r=".6"/>
<circle cx="91.7" cy="104.6" r=".6"/>
<circle cx="114.7" cy="118.5" r=".85"/>
<circle cx="117.2" cy="118.5" r=".85"/>
<circle cx="114.7" cy="121" r=".85"/>
<circle cx="114.7" cy="123.6" r=".85"/>
<circle cx="114.7" cy="126.1" r=".85"/>
<circle cx="114.7" cy="128.6" r=".85"/>
<circle cx="117.2" cy="121" r=".85"/>
<circle cx="117.2" cy="126.1" r=".85"/>
<circle cx="117.2" cy="123.6" r=".85"/>
<circle cx="141.9" cy="136" r=".5"/>
<circle cx="143.1" cy="136" r=".5"/>
<circle cx="143.1" cy="137.3" r=".5"/>
<circle cx="144.4" cy="136" r=".5"/>
<circle cx="144.4" cy="137.3" r=".5"/>
<circle cx="145.7" cy="137.3" r=".5"/>
<circle cx="145.7" cy="136" r=".5"/>
<circle cx="146.9" cy="136" r=".5"/>
<circle cx="146.9" cy="137.3" r=".5"/>
<circle cx="165.5" cy="137" r=".85"/>
</g>
<path d="M89 104.6h.4" fill="none" stroke="#000" stroke-width="1.2"/>
<path d="M227.6 91.7h1.7v9.9h-1.7zM227.6 93.3h1.7M227.6 96.6h1.7M227.6 95h1.7M227.6 99.9h1.7" fill="none" stroke="#000" stroke-width=".14"/>
<path d="M90.5 98.3l-.1 3.9M90.4 106.2v4.9" fill="none" stroke="#000" stroke-width=".76"/>
<path d="M90.4 102.2v1.2M90.4 105.9v1.1" fill="none" stroke="#000" stroke-width="1.3"/>
<use href="#words"/>
</svg>
